# Generated deterministically by seda-macro-lef-normalizer-v1; recipe orfs-asap7-fakeram-m4-v1.
VERSION 5.8 ;
BUSBITCHARS "[]" ;
DIVIDERCHAR "/" ;

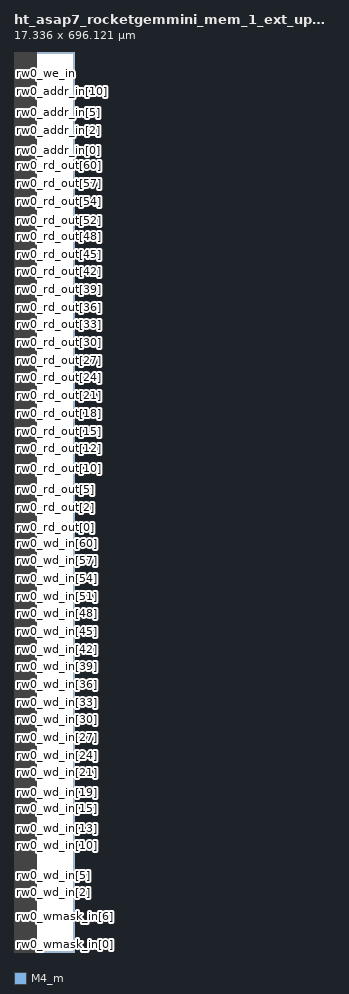
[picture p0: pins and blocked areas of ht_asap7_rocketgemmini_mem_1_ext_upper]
MACRO ht_asap7_rocketgemmini_mem_1_ext_upper
  FOREIGN ht_asap7_rocketgemmini_mem_1_ext_upper 0 0 ;
  CLASS COVER ;
  ORIGIN 0 0 ;
  SIZE 17.336 BY 696.121 ;
  SYMMETRY X Y R90 ;
  PIN rw0_wmask_in[0]
    DIRECTION INPUT ;
    USE SIGNAL ;
    SHAPE ABUTMENT ;
    PORT
      LAYER M4_m ;
      RECT 0 0.048 0.024 0.072 ;
    END
  END rw0_wmask_in[0]
  PIN rw0_wmask_in[1]
    DIRECTION INPUT ;
    USE SIGNAL ;
    SHAPE ABUTMENT ;
    PORT
      LAYER M4_m ;
      RECT 0 4.608 0.024 4.632 ;
    END
  END rw0_wmask_in[1]
  PIN rw0_wmask_in[2]
    DIRECTION INPUT ;
    USE SIGNAL ;
    SHAPE ABUTMENT ;
    PORT
      LAYER M4_m ;
      RECT 0 9.168 0.024 9.192 ;
    END
  END rw0_wmask_in[2]
  PIN rw0_wmask_in[3]
    DIRECTION INPUT ;
    USE SIGNAL ;
    SHAPE ABUTMENT ;
    PORT
      LAYER M4_m ;
      RECT 0 13.728 0.024 13.752 ;
    END
  END rw0_wmask_in[3]
  PIN rw0_wmask_in[4]
    DIRECTION INPUT ;
    USE SIGNAL ;
    SHAPE ABUTMENT ;
    PORT
      LAYER M4_m ;
      RECT 0 18.288 0.024 18.312 ;
    END
  END rw0_wmask_in[4]
  PIN rw0_wmask_in[5]
    DIRECTION INPUT ;
    USE SIGNAL ;
    SHAPE ABUTMENT ;
    PORT
      LAYER M4_m ;
      RECT 0 22.848 0.024 22.872 ;
    END
  END rw0_wmask_in[5]
  PIN rw0_wmask_in[6]
    DIRECTION INPUT ;
    USE SIGNAL ;
    SHAPE ABUTMENT ;
    PORT
      LAYER M4_m ;
      RECT 0 27.408 0.024 27.432 ;
    END
  END rw0_wmask_in[6]
  PIN rw0_wmask_in[7]
    DIRECTION INPUT ;
    USE SIGNAL ;
    SHAPE ABUTMENT ;
    PORT
      LAYER M4_m ;
      RECT 0 31.968 0.024 31.992 ;
    END
  END rw0_wmask_in[7]
  PIN rw0_wd_in[0]
    DIRECTION INPUT ;
    USE SIGNAL ;
    SHAPE ABUTMENT ;
    PORT
      LAYER M4_m ;
      RECT 0 36.528 0.024 36.552 ;
    END
  END rw0_wd_in[0]
  PIN rw0_wd_in[1]
    DIRECTION INPUT ;
    USE SIGNAL ;
    SHAPE ABUTMENT ;
    PORT
      LAYER M4_m ;
      RECT 0 41.088 0.024 41.112 ;
    END
  END rw0_wd_in[1]
  PIN rw0_wd_in[2]
    DIRECTION INPUT ;
    USE SIGNAL ;
    SHAPE ABUTMENT ;
    PORT
      LAYER M4_m ;
      RECT 0 45.648 0.024 45.672 ;
    END
  END rw0_wd_in[2]
  PIN rw0_wd_in[3]
    DIRECTION INPUT ;
    USE SIGNAL ;
    SHAPE ABUTMENT ;
    PORT
      LAYER M4_m ;
      RECT 0 50.208 0.024 50.232 ;
    END
  END rw0_wd_in[3]
  PIN rw0_wd_in[4]
    DIRECTION INPUT ;
    USE SIGNAL ;
    SHAPE ABUTMENT ;
    PORT
      LAYER M4_m ;
      RECT 0 54.768 0.024 54.792 ;
    END
  END rw0_wd_in[4]
  PIN rw0_wd_in[5]
    DIRECTION INPUT ;
    USE SIGNAL ;
    SHAPE ABUTMENT ;
    PORT
      LAYER M4_m ;
      RECT 0 59.328 0.024 59.352 ;
    END
  END rw0_wd_in[5]
  PIN rw0_wd_in[6]
    DIRECTION INPUT ;
    USE SIGNAL ;
    SHAPE ABUTMENT ;
    PORT
      LAYER M4_m ;
      RECT 0 63.888 0.024 63.912 ;
    END
  END rw0_wd_in[6]
  PIN rw0_wd_in[7]
    DIRECTION INPUT ;
    USE SIGNAL ;
    SHAPE ABUTMENT ;
    PORT
      LAYER M4_m ;
      RECT 0 68.448 0.024 68.472 ;
    END
  END rw0_wd_in[7]
  PIN rw0_wd_in[8]
    DIRECTION INPUT ;
    USE SIGNAL ;
    SHAPE ABUTMENT ;
    PORT
      LAYER M4_m ;
      RECT 0 73.008 0.024 73.032 ;
    END
  END rw0_wd_in[8]
  PIN rw0_wd_in[9]
    DIRECTION INPUT ;
    USE SIGNAL ;
    SHAPE ABUTMENT ;
    PORT
      LAYER M4_m ;
      RECT 0 77.568 0.024 77.592 ;
    END
  END rw0_wd_in[9]
  PIN rw0_wd_in[10]
    DIRECTION INPUT ;
    USE SIGNAL ;
    SHAPE ABUTMENT ;
    PORT
      LAYER M4_m ;
      RECT 0 82.128 0.024 82.152 ;
    END
  END rw0_wd_in[10]
  PIN rw0_wd_in[11]
    DIRECTION INPUT ;
    USE SIGNAL ;
    SHAPE ABUTMENT ;
    PORT
      LAYER M4_m ;
      RECT 0 86.688 0.024 86.712 ;
    END
  END rw0_wd_in[11]
  PIN rw0_wd_in[12]
    DIRECTION INPUT ;
    USE SIGNAL ;
    SHAPE ABUTMENT ;
    PORT
      LAYER M4_m ;
      RECT 0 91.248 0.024 91.272 ;
    END
  END rw0_wd_in[12]
  PIN rw0_wd_in[13]
    DIRECTION INPUT ;
    USE SIGNAL ;
    SHAPE ABUTMENT ;
    PORT
      LAYER M4_m ;
      RECT 0 95.808 0.024 95.832 ;
    END
  END rw0_wd_in[13]
  PIN rw0_wd_in[14]
    DIRECTION INPUT ;
    USE SIGNAL ;
    SHAPE ABUTMENT ;
    PORT
      LAYER M4_m ;
      RECT 0 100.368 0.024 100.392 ;
    END
  END rw0_wd_in[14]
  PIN rw0_wd_in[15]
    DIRECTION INPUT ;
    USE SIGNAL ;
    SHAPE ABUTMENT ;
    PORT
      LAYER M4_m ;
      RECT 0 104.928 0.024 104.952 ;
    END
  END rw0_wd_in[15]
  PIN rw0_wd_in[16]
    DIRECTION INPUT ;
    USE SIGNAL ;
    SHAPE ABUTMENT ;
    PORT
      LAYER M4_m ;
      RECT 0 109.488 0.024 109.512 ;
    END
  END rw0_wd_in[16]
  PIN rw0_wd_in[17]
    DIRECTION INPUT ;
    USE SIGNAL ;
    SHAPE ABUTMENT ;
    PORT
      LAYER M4_m ;
      RECT 0 114.048 0.024 114.072 ;
    END
  END rw0_wd_in[17]
  PIN rw0_wd_in[18]
    DIRECTION INPUT ;
    USE SIGNAL ;
    SHAPE ABUTMENT ;
    PORT
      LAYER M4_m ;
      RECT 0 118.608 0.024 118.632 ;
    END
  END rw0_wd_in[18]
  PIN rw0_wd_in[19]
    DIRECTION INPUT ;
    USE SIGNAL ;
    SHAPE ABUTMENT ;
    PORT
      LAYER M4_m ;
      RECT 0 123.168 0.024 123.192 ;
    END
  END rw0_wd_in[19]
  PIN rw0_wd_in[20]
    DIRECTION INPUT ;
    USE SIGNAL ;
    SHAPE ABUTMENT ;
    PORT
      LAYER M4_m ;
      RECT 0 127.728 0.024 127.752 ;
    END
  END rw0_wd_in[20]
  PIN rw0_wd_in[21]
    DIRECTION INPUT ;
    USE SIGNAL ;
    SHAPE ABUTMENT ;
    PORT
      LAYER M4_m ;
      RECT 0 132.288 0.024 132.312 ;
    END
  END rw0_wd_in[21]
  PIN rw0_wd_in[22]
    DIRECTION INPUT ;
    USE SIGNAL ;
    SHAPE ABUTMENT ;
    PORT
      LAYER M4_m ;
      RECT 0 136.848 0.024 136.872 ;
    END
  END rw0_wd_in[22]
  PIN rw0_wd_in[23]
    DIRECTION INPUT ;
    USE SIGNAL ;
    SHAPE ABUTMENT ;
    PORT
      LAYER M4_m ;
      RECT 0 141.408 0.024 141.432 ;
    END
  END rw0_wd_in[23]
  PIN rw0_wd_in[24]
    DIRECTION INPUT ;
    USE SIGNAL ;
    SHAPE ABUTMENT ;
    PORT
      LAYER M4_m ;
      RECT 0 145.968 0.024 145.992 ;
    END
  END rw0_wd_in[24]
  PIN rw0_wd_in[25]
    DIRECTION INPUT ;
    USE SIGNAL ;
    SHAPE ABUTMENT ;
    PORT
      LAYER M4_m ;
      RECT 0 150.528 0.024 150.552 ;
    END
  END rw0_wd_in[25]
  PIN rw0_wd_in[26]
    DIRECTION INPUT ;
    USE SIGNAL ;
    SHAPE ABUTMENT ;
    PORT
      LAYER M4_m ;
      RECT 0 155.088 0.024 155.112 ;
    END
  END rw0_wd_in[26]
  PIN rw0_wd_in[27]
    DIRECTION INPUT ;
    USE SIGNAL ;
    SHAPE ABUTMENT ;
    PORT
      LAYER M4_m ;
      RECT 0 159.648 0.024 159.672 ;
    END
  END rw0_wd_in[27]
  PIN rw0_wd_in[28]
    DIRECTION INPUT ;
    USE SIGNAL ;
    SHAPE ABUTMENT ;
    PORT
      LAYER M4_m ;
      RECT 0 164.208 0.024 164.232 ;
    END
  END rw0_wd_in[28]
  PIN rw0_wd_in[29]
    DIRECTION INPUT ;
    USE SIGNAL ;
    SHAPE ABUTMENT ;
    PORT
      LAYER M4_m ;
      RECT 0 168.768 0.024 168.792 ;
    END
  END rw0_wd_in[29]
  PIN rw0_wd_in[30]
    DIRECTION INPUT ;
    USE SIGNAL ;
    SHAPE ABUTMENT ;
    PORT
      LAYER M4_m ;
      RECT 0 173.328 0.024 173.352 ;
    END
  END rw0_wd_in[30]
  PIN rw0_wd_in[31]
    DIRECTION INPUT ;
    USE SIGNAL ;
    SHAPE ABUTMENT ;
    PORT
      LAYER M4_m ;
      RECT 0 177.888 0.024 177.912 ;
    END
  END rw0_wd_in[31]
  PIN rw0_wd_in[32]
    DIRECTION INPUT ;
    USE SIGNAL ;
    SHAPE ABUTMENT ;
    PORT
      LAYER M4_m ;
      RECT 0 182.448 0.024 182.472 ;
    END
  END rw0_wd_in[32]
  PIN rw0_wd_in[33]
    DIRECTION INPUT ;
    USE SIGNAL ;
    SHAPE ABUTMENT ;
    PORT
      LAYER M4_m ;
      RECT 0 187.008 0.024 187.032 ;
    END
  END rw0_wd_in[33]
  PIN rw0_wd_in[34]
    DIRECTION INPUT ;
    USE SIGNAL ;
    SHAPE ABUTMENT ;
    PORT
      LAYER M4_m ;
      RECT 0 191.568 0.024 191.592 ;
    END
  END rw0_wd_in[34]
  PIN rw0_wd_in[35]
    DIRECTION INPUT ;
    USE SIGNAL ;
    SHAPE ABUTMENT ;
    PORT
      LAYER M4_m ;
      RECT 0 196.128 0.024 196.152 ;
    END
  END rw0_wd_in[35]
  PIN rw0_wd_in[36]
    DIRECTION INPUT ;
    USE SIGNAL ;
    SHAPE ABUTMENT ;
    PORT
      LAYER M4_m ;
      RECT 0 200.688 0.024 200.712 ;
    END
  END rw0_wd_in[36]
  PIN rw0_wd_in[37]
    DIRECTION INPUT ;
    USE SIGNAL ;
    SHAPE ABUTMENT ;
    PORT
      LAYER M4_m ;
      RECT 0 205.248 0.024 205.272 ;
    END
  END rw0_wd_in[37]
  PIN rw0_wd_in[38]
    DIRECTION INPUT ;
    USE SIGNAL ;
    SHAPE ABUTMENT ;
    PORT
      LAYER M4_m ;
      RECT 0 209.808 0.024 209.832 ;
    END
  END rw0_wd_in[38]
  PIN rw0_wd_in[39]
    DIRECTION INPUT ;
    USE SIGNAL ;
    SHAPE ABUTMENT ;
    PORT
      LAYER M4_m ;
      RECT 0 214.368 0.024 214.392 ;
    END
  END rw0_wd_in[39]
  PIN rw0_wd_in[40]
    DIRECTION INPUT ;
    USE SIGNAL ;
    SHAPE ABUTMENT ;
    PORT
      LAYER M4_m ;
      RECT 0 218.928 0.024 218.952 ;
    END
  END rw0_wd_in[40]
  PIN rw0_wd_in[41]
    DIRECTION INPUT ;
    USE SIGNAL ;
    SHAPE ABUTMENT ;
    PORT
      LAYER M4_m ;
      RECT 0 223.488 0.024 223.512 ;
    END
  END rw0_wd_in[41]
  PIN rw0_wd_in[42]
    DIRECTION INPUT ;
    USE SIGNAL ;
    SHAPE ABUTMENT ;
    PORT
      LAYER M4_m ;
      RECT 0 228.048 0.024 228.072 ;
    END
  END rw0_wd_in[42]
  PIN rw0_wd_in[43]
    DIRECTION INPUT ;
    USE SIGNAL ;
    SHAPE ABUTMENT ;
    PORT
      LAYER M4_m ;
      RECT 0 232.608 0.024 232.632 ;
    END
  END rw0_wd_in[43]
  PIN rw0_wd_in[44]
    DIRECTION INPUT ;
    USE SIGNAL ;
    SHAPE ABUTMENT ;
    PORT
      LAYER M4_m ;
      RECT 0 237.168 0.024 237.192 ;
    END
  END rw0_wd_in[44]
  PIN rw0_wd_in[45]
    DIRECTION INPUT ;
    USE SIGNAL ;
    SHAPE ABUTMENT ;
    PORT
      LAYER M4_m ;
      RECT 0 241.728 0.024 241.752 ;
    END
  END rw0_wd_in[45]
  PIN rw0_wd_in[46]
    DIRECTION INPUT ;
    USE SIGNAL ;
    SHAPE ABUTMENT ;
    PORT
      LAYER M4_m ;
      RECT 0 246.288 0.024 246.312 ;
    END
  END rw0_wd_in[46]
  PIN rw0_wd_in[47]
    DIRECTION INPUT ;
    USE SIGNAL ;
    SHAPE ABUTMENT ;
    PORT
      LAYER M4_m ;
      RECT 0 250.848 0.024 250.872 ;
    END
  END rw0_wd_in[47]
  PIN rw0_wd_in[48]
    DIRECTION INPUT ;
    USE SIGNAL ;
    SHAPE ABUTMENT ;
    PORT
      LAYER M4_m ;
      RECT 0 255.408 0.024 255.432 ;
    END
  END rw0_wd_in[48]
  PIN rw0_wd_in[49]
    DIRECTION INPUT ;
    USE SIGNAL ;
    SHAPE ABUTMENT ;
    PORT
      LAYER M4_m ;
      RECT 0 259.968 0.024 259.992 ;
    END
  END rw0_wd_in[49]
  PIN rw0_wd_in[50]
    DIRECTION INPUT ;
    USE SIGNAL ;
    SHAPE ABUTMENT ;
    PORT
      LAYER M4_m ;
      RECT 0 264.528 0.024 264.552 ;
    END
  END rw0_wd_in[50]
  PIN rw0_wd_in[51]
    DIRECTION INPUT ;
    USE SIGNAL ;
    SHAPE ABUTMENT ;
    PORT
      LAYER M4_m ;
      RECT 0 269.088 0.024 269.112 ;
    END
  END rw0_wd_in[51]
  PIN rw0_wd_in[52]
    DIRECTION INPUT ;
    USE SIGNAL ;
    SHAPE ABUTMENT ;
    PORT
      LAYER M4_m ;
      RECT 0 273.648 0.024 273.672 ;
    END
  END rw0_wd_in[52]
  PIN rw0_wd_in[53]
    DIRECTION INPUT ;
    USE SIGNAL ;
    SHAPE ABUTMENT ;
    PORT
      LAYER M4_m ;
      RECT 0 278.208 0.024 278.232 ;
    END
  END rw0_wd_in[53]
  PIN rw0_wd_in[54]
    DIRECTION INPUT ;
    USE SIGNAL ;
    SHAPE ABUTMENT ;
    PORT
      LAYER M4_m ;
      RECT 0 282.768 0.024 282.792 ;
    END
  END rw0_wd_in[54]
  PIN rw0_wd_in[55]
    DIRECTION INPUT ;
    USE SIGNAL ;
    SHAPE ABUTMENT ;
    PORT
      LAYER M4_m ;
      RECT 0 287.328 0.024 287.352 ;
    END
  END rw0_wd_in[55]
  PIN rw0_wd_in[56]
    DIRECTION INPUT ;
    USE SIGNAL ;
    SHAPE ABUTMENT ;
    PORT
      LAYER M4_m ;
      RECT 0 291.888 0.024 291.912 ;
    END
  END rw0_wd_in[56]
  PIN rw0_wd_in[57]
    DIRECTION INPUT ;
    USE SIGNAL ;
    SHAPE ABUTMENT ;
    PORT
      LAYER M4_m ;
      RECT 0 296.448 0.024 296.472 ;
    END
  END rw0_wd_in[57]
  PIN rw0_wd_in[58]
    DIRECTION INPUT ;
    USE SIGNAL ;
    SHAPE ABUTMENT ;
    PORT
      LAYER M4_m ;
      RECT 0 301.008 0.024 301.032 ;
    END
  END rw0_wd_in[58]
  PIN rw0_wd_in[59]
    DIRECTION INPUT ;
    USE SIGNAL ;
    SHAPE ABUTMENT ;
    PORT
      LAYER M4_m ;
      RECT 0 305.568 0.024 305.592 ;
    END
  END rw0_wd_in[59]
  PIN rw0_wd_in[60]
    DIRECTION INPUT ;
    USE SIGNAL ;
    SHAPE ABUTMENT ;
    PORT
      LAYER M4_m ;
      RECT 0 310.128 0.024 310.152 ;
    END
  END rw0_wd_in[60]
  PIN rw0_wd_in[61]
    DIRECTION INPUT ;
    USE SIGNAL ;
    SHAPE ABUTMENT ;
    PORT
      LAYER M4_m ;
      RECT 0 314.688 0.024 314.712 ;
    END
  END rw0_wd_in[61]
  PIN rw0_wd_in[62]
    DIRECTION INPUT ;
    USE SIGNAL ;
    SHAPE ABUTMENT ;
    PORT
      LAYER M4_m ;
      RECT 0 319.248 0.024 319.272 ;
    END
  END rw0_wd_in[62]
  PIN rw0_wd_in[63]
    DIRECTION INPUT ;
    USE SIGNAL ;
    SHAPE ABUTMENT ;
    PORT
      LAYER M4_m ;
      RECT 0 323.808 0.024 323.832 ;
    END
  END rw0_wd_in[63]
  PIN rw0_rd_out[0]
    DIRECTION OUTPUT ;
    USE SIGNAL ;
    SHAPE ABUTMENT ;
    PORT
      LAYER M4_m ;
      RECT 0 328.368 0.024 328.392 ;
    END
  END rw0_rd_out[0]
  PIN rw0_rd_out[1]
    DIRECTION OUTPUT ;
    USE SIGNAL ;
    SHAPE ABUTMENT ;
    PORT
      LAYER M4_m ;
      RECT 0 332.928 0.024 332.952 ;
    END
  END rw0_rd_out[1]
  PIN rw0_rd_out[2]
    DIRECTION OUTPUT ;
    USE SIGNAL ;
    SHAPE ABUTMENT ;
    PORT
      LAYER M4_m ;
      RECT 0 337.488 0.024 337.512 ;
    END
  END rw0_rd_out[2]
  PIN rw0_rd_out[3]
    DIRECTION OUTPUT ;
    USE SIGNAL ;
    SHAPE ABUTMENT ;
    PORT
      LAYER M4_m ;
      RECT 0 342.048 0.024 342.072 ;
    END
  END rw0_rd_out[3]
  PIN rw0_rd_out[4]
    DIRECTION OUTPUT ;
    USE SIGNAL ;
    SHAPE ABUTMENT ;
    PORT
      LAYER M4_m ;
      RECT 0 346.608 0.024 346.632 ;
    END
  END rw0_rd_out[4]
  PIN rw0_rd_out[5]
    DIRECTION OUTPUT ;
    USE SIGNAL ;
    SHAPE ABUTMENT ;
    PORT
      LAYER M4_m ;
      RECT 0 351.168 0.024 351.192 ;
    END
  END rw0_rd_out[5]
  PIN rw0_rd_out[6]
    DIRECTION OUTPUT ;
    USE SIGNAL ;
    SHAPE ABUTMENT ;
    PORT
      LAYER M4_m ;
      RECT 0 355.728 0.024 355.752 ;
    END
  END rw0_rd_out[6]
  PIN rw0_rd_out[7]
    DIRECTION OUTPUT ;
    USE SIGNAL ;
    SHAPE ABUTMENT ;
    PORT
      LAYER M4_m ;
      RECT 0 360.288 0.024 360.312 ;
    END
  END rw0_rd_out[7]
  PIN rw0_rd_out[8]
    DIRECTION OUTPUT ;
    USE SIGNAL ;
    SHAPE ABUTMENT ;
    PORT
      LAYER M4_m ;
      RECT 0 364.848 0.024 364.872 ;
    END
  END rw0_rd_out[8]
  PIN rw0_rd_out[9]
    DIRECTION OUTPUT ;
    USE SIGNAL ;
    SHAPE ABUTMENT ;
    PORT
      LAYER M4_m ;
      RECT 0 369.408 0.024 369.432 ;
    END
  END rw0_rd_out[9]
  PIN rw0_rd_out[10]
    DIRECTION OUTPUT ;
    USE SIGNAL ;
    SHAPE ABUTMENT ;
    PORT
      LAYER M4_m ;
      RECT 0 373.968 0.024 373.992 ;
    END
  END rw0_rd_out[10]
  PIN rw0_rd_out[11]
    DIRECTION OUTPUT ;
    USE SIGNAL ;
    SHAPE ABUTMENT ;
    PORT
      LAYER M4_m ;
      RECT 0 378.528 0.024 378.552 ;
    END
  END rw0_rd_out[11]
  PIN rw0_rd_out[12]
    DIRECTION OUTPUT ;
    USE SIGNAL ;
    SHAPE ABUTMENT ;
    PORT
      LAYER M4_m ;
      RECT 0 383.088 0.024 383.112 ;
    END
  END rw0_rd_out[12]
  PIN rw0_rd_out[13]
    DIRECTION OUTPUT ;
    USE SIGNAL ;
    SHAPE ABUTMENT ;
    PORT
      LAYER M4_m ;
      RECT 0 387.648 0.024 387.672 ;
    END
  END rw0_rd_out[13]
  PIN rw0_rd_out[14]
    DIRECTION OUTPUT ;
    USE SIGNAL ;
    SHAPE ABUTMENT ;
    PORT
      LAYER M4_m ;
      RECT 0 392.208 0.024 392.232 ;
    END
  END rw0_rd_out[14]
  PIN rw0_rd_out[15]
    DIRECTION OUTPUT ;
    USE SIGNAL ;
    SHAPE ABUTMENT ;
    PORT
      LAYER M4_m ;
      RECT 0 396.768 0.024 396.792 ;
    END
  END rw0_rd_out[15]
  PIN rw0_rd_out[16]
    DIRECTION OUTPUT ;
    USE SIGNAL ;
    SHAPE ABUTMENT ;
    PORT
      LAYER M4_m ;
      RECT 0 401.328 0.024 401.352 ;
    END
  END rw0_rd_out[16]
  PIN rw0_rd_out[17]
    DIRECTION OUTPUT ;
    USE SIGNAL ;
    SHAPE ABUTMENT ;
    PORT
      LAYER M4_m ;
      RECT 0 405.888 0.024 405.912 ;
    END
  END rw0_rd_out[17]
  PIN rw0_rd_out[18]
    DIRECTION OUTPUT ;
    USE SIGNAL ;
    SHAPE ABUTMENT ;
    PORT
      LAYER M4_m ;
      RECT 0 410.448 0.024 410.472 ;
    END
  END rw0_rd_out[18]
  PIN rw0_rd_out[19]
    DIRECTION OUTPUT ;
    USE SIGNAL ;
    SHAPE ABUTMENT ;
    PORT
      LAYER M4_m ;
      RECT 0 415.008 0.024 415.032 ;
    END
  END rw0_rd_out[19]
  PIN rw0_rd_out[20]
    DIRECTION OUTPUT ;
    USE SIGNAL ;
    SHAPE ABUTMENT ;
    PORT
      LAYER M4_m ;
      RECT 0 419.568 0.024 419.592 ;
    END
  END rw0_rd_out[20]
  PIN rw0_rd_out[21]
    DIRECTION OUTPUT ;
    USE SIGNAL ;
    SHAPE ABUTMENT ;
    PORT
      LAYER M4_m ;
      RECT 0 424.128 0.024 424.152 ;
    END
  END rw0_rd_out[21]
  PIN rw0_rd_out[22]
    DIRECTION OUTPUT ;
    USE SIGNAL ;
    SHAPE ABUTMENT ;
    PORT
      LAYER M4_m ;
      RECT 0 428.688 0.024 428.712 ;
    END
  END rw0_rd_out[22]
  PIN rw0_rd_out[23]
    DIRECTION OUTPUT ;
    USE SIGNAL ;
    SHAPE ABUTMENT ;
    PORT
      LAYER M4_m ;
      RECT 0 433.248 0.024 433.272 ;
    END
  END rw0_rd_out[23]
  PIN rw0_rd_out[24]
    DIRECTION OUTPUT ;
    USE SIGNAL ;
    SHAPE ABUTMENT ;
    PORT
      LAYER M4_m ;
      RECT 0 437.808 0.024 437.832 ;
    END
  END rw0_rd_out[24]
  PIN rw0_rd_out[25]
    DIRECTION OUTPUT ;
    USE SIGNAL ;
    SHAPE ABUTMENT ;
    PORT
      LAYER M4_m ;
      RECT 0 442.368 0.024 442.392 ;
    END
  END rw0_rd_out[25]
  PIN rw0_rd_out[26]
    DIRECTION OUTPUT ;
    USE SIGNAL ;
    SHAPE ABUTMENT ;
    PORT
      LAYER M4_m ;
      RECT 0 446.928 0.024 446.952 ;
    END
  END rw0_rd_out[26]
  PIN rw0_rd_out[27]
    DIRECTION OUTPUT ;
    USE SIGNAL ;
    SHAPE ABUTMENT ;
    PORT
      LAYER M4_m ;
      RECT 0 451.488 0.024 451.512 ;
    END
  END rw0_rd_out[27]
  PIN rw0_rd_out[28]
    DIRECTION OUTPUT ;
    USE SIGNAL ;
    SHAPE ABUTMENT ;
    PORT
      LAYER M4_m ;
      RECT 0 456.048 0.024 456.072 ;
    END
  END rw0_rd_out[28]
  PIN rw0_rd_out[29]
    DIRECTION OUTPUT ;
    USE SIGNAL ;
    SHAPE ABUTMENT ;
    PORT
      LAYER M4_m ;
      RECT 0 460.608 0.024 460.632 ;
    END
  END rw0_rd_out[29]
  PIN rw0_rd_out[30]
    DIRECTION OUTPUT ;
    USE SIGNAL ;
    SHAPE ABUTMENT ;
    PORT
      LAYER M4_m ;
      RECT 0 465.168 0.024 465.192 ;
    END
  END rw0_rd_out[30]
  PIN rw0_rd_out[31]
    DIRECTION OUTPUT ;
    USE SIGNAL ;
    SHAPE ABUTMENT ;
    PORT
      LAYER M4_m ;
      RECT 0 469.728 0.024 469.752 ;
    END
  END rw0_rd_out[31]
  PIN rw0_rd_out[32]
    DIRECTION OUTPUT ;
    USE SIGNAL ;
    SHAPE ABUTMENT ;
    PORT
      LAYER M4_m ;
      RECT 0 474.288 0.024 474.312 ;
    END
  END rw0_rd_out[32]
  PIN rw0_rd_out[33]
    DIRECTION OUTPUT ;
    USE SIGNAL ;
    SHAPE ABUTMENT ;
    PORT
      LAYER M4_m ;
      RECT 0 478.848 0.024 478.872 ;
    END
  END rw0_rd_out[33]
  PIN rw0_rd_out[34]
    DIRECTION OUTPUT ;
    USE SIGNAL ;
    SHAPE ABUTMENT ;
    PORT
      LAYER M4_m ;
      RECT 0 483.408 0.024 483.432 ;
    END
  END rw0_rd_out[34]
  PIN rw0_rd_out[35]
    DIRECTION OUTPUT ;
    USE SIGNAL ;
    SHAPE ABUTMENT ;
    PORT
      LAYER M4_m ;
      RECT 0 487.968 0.024 487.992 ;
    END
  END rw0_rd_out[35]
  PIN rw0_rd_out[36]
    DIRECTION OUTPUT ;
    USE SIGNAL ;
    SHAPE ABUTMENT ;
    PORT
      LAYER M4_m ;
      RECT 0 492.528 0.024 492.552 ;
    END
  END rw0_rd_out[36]
  PIN rw0_rd_out[37]
    DIRECTION OUTPUT ;
    USE SIGNAL ;
    SHAPE ABUTMENT ;
    PORT
      LAYER M4_m ;
      RECT 0 497.088 0.024 497.112 ;
    END
  END rw0_rd_out[37]
  PIN rw0_rd_out[38]
    DIRECTION OUTPUT ;
    USE SIGNAL ;
    SHAPE ABUTMENT ;
    PORT
      LAYER M4_m ;
      RECT 0 501.648 0.024 501.672 ;
    END
  END rw0_rd_out[38]
  PIN rw0_rd_out[39]
    DIRECTION OUTPUT ;
    USE SIGNAL ;
    SHAPE ABUTMENT ;
    PORT
      LAYER M4_m ;
      RECT 0 506.208 0.024 506.232 ;
    END
  END rw0_rd_out[39]
  PIN rw0_rd_out[40]
    DIRECTION OUTPUT ;
    USE SIGNAL ;
    SHAPE ABUTMENT ;
    PORT
      LAYER M4_m ;
      RECT 0 510.768 0.024 510.792 ;
    END
  END rw0_rd_out[40]
  PIN rw0_rd_out[41]
    DIRECTION OUTPUT ;
    USE SIGNAL ;
    SHAPE ABUTMENT ;
    PORT
      LAYER M4_m ;
      RECT 0 515.328 0.024 515.352 ;
    END
  END rw0_rd_out[41]
  PIN rw0_rd_out[42]
    DIRECTION OUTPUT ;
    USE SIGNAL ;
    SHAPE ABUTMENT ;
    PORT
      LAYER M4_m ;
      RECT 0 519.888 0.024 519.912 ;
    END
  END rw0_rd_out[42]
  PIN rw0_rd_out[43]
    DIRECTION OUTPUT ;
    USE SIGNAL ;
    SHAPE ABUTMENT ;
    PORT
      LAYER M4_m ;
      RECT 0 524.448 0.024 524.472 ;
    END
  END rw0_rd_out[43]
  PIN rw0_rd_out[44]
    DIRECTION OUTPUT ;
    USE SIGNAL ;
    SHAPE ABUTMENT ;
    PORT
      LAYER M4_m ;
      RECT 0 529.008 0.024 529.032 ;
    END
  END rw0_rd_out[44]
  PIN rw0_rd_out[45]
    DIRECTION OUTPUT ;
    USE SIGNAL ;
    SHAPE ABUTMENT ;
    PORT
      LAYER M4_m ;
      RECT 0 533.568 0.024 533.592 ;
    END
  END rw0_rd_out[45]
  PIN rw0_rd_out[46]
    DIRECTION OUTPUT ;
    USE SIGNAL ;
    SHAPE ABUTMENT ;
    PORT
      LAYER M4_m ;
      RECT 0 538.128 0.024 538.152 ;
    END
  END rw0_rd_out[46]
  PIN rw0_rd_out[47]
    DIRECTION OUTPUT ;
    USE SIGNAL ;
    SHAPE ABUTMENT ;
    PORT
      LAYER M4_m ;
      RECT 0 542.688 0.024 542.712 ;
    END
  END rw0_rd_out[47]
  PIN rw0_rd_out[48]
    DIRECTION OUTPUT ;
    USE SIGNAL ;
    SHAPE ABUTMENT ;
    PORT
      LAYER M4_m ;
      RECT 0 547.248 0.024 547.272 ;
    END
  END rw0_rd_out[48]
  PIN rw0_rd_out[49]
    DIRECTION OUTPUT ;
    USE SIGNAL ;
    SHAPE ABUTMENT ;
    PORT
      LAYER M4_m ;
      RECT 0 551.808 0.024 551.832 ;
    END
  END rw0_rd_out[49]
  PIN rw0_rd_out[50]
    DIRECTION OUTPUT ;
    USE SIGNAL ;
    SHAPE ABUTMENT ;
    PORT
      LAYER M4_m ;
      RECT 0 556.368 0.024 556.392 ;
    END
  END rw0_rd_out[50]
  PIN rw0_rd_out[51]
    DIRECTION OUTPUT ;
    USE SIGNAL ;
    SHAPE ABUTMENT ;
    PORT
      LAYER M4_m ;
      RECT 0 560.928 0.024 560.952 ;
    END
  END rw0_rd_out[51]
  PIN rw0_rd_out[52]
    DIRECTION OUTPUT ;
    USE SIGNAL ;
    SHAPE ABUTMENT ;
    PORT
      LAYER M4_m ;
      RECT 0 565.488 0.024 565.512 ;
    END
  END rw0_rd_out[52]
  PIN rw0_rd_out[53]
    DIRECTION OUTPUT ;
    USE SIGNAL ;
    SHAPE ABUTMENT ;
    PORT
      LAYER M4_m ;
      RECT 0 570.048 0.024 570.072 ;
    END
  END rw0_rd_out[53]
  PIN rw0_rd_out[54]
    DIRECTION OUTPUT ;
    USE SIGNAL ;
    SHAPE ABUTMENT ;
    PORT
      LAYER M4_m ;
      RECT 0 574.608 0.024 574.632 ;
    END
  END rw0_rd_out[54]
  PIN rw0_rd_out[55]
    DIRECTION OUTPUT ;
    USE SIGNAL ;
    SHAPE ABUTMENT ;
    PORT
      LAYER M4_m ;
      RECT 0 579.168 0.024 579.192 ;
    END
  END rw0_rd_out[55]
  PIN rw0_rd_out[56]
    DIRECTION OUTPUT ;
    USE SIGNAL ;
    SHAPE ABUTMENT ;
    PORT
      LAYER M4_m ;
      RECT 0 583.728 0.024 583.752 ;
    END
  END rw0_rd_out[56]
  PIN rw0_rd_out[57]
    DIRECTION OUTPUT ;
    USE SIGNAL ;
    SHAPE ABUTMENT ;
    PORT
      LAYER M4_m ;
      RECT 0 588.288 0.024 588.312 ;
    END
  END rw0_rd_out[57]
  PIN rw0_rd_out[58]
    DIRECTION OUTPUT ;
    USE SIGNAL ;
    SHAPE ABUTMENT ;
    PORT
      LAYER M4_m ;
      RECT 0 592.848 0.024 592.872 ;
    END
  END rw0_rd_out[58]
  PIN rw0_rd_out[59]
    DIRECTION OUTPUT ;
    USE SIGNAL ;
    SHAPE ABUTMENT ;
    PORT
      LAYER M4_m ;
      RECT 0 597.408 0.024 597.432 ;
    END
  END rw0_rd_out[59]
  PIN rw0_rd_out[60]
    DIRECTION OUTPUT ;
    USE SIGNAL ;
    SHAPE ABUTMENT ;
    PORT
      LAYER M4_m ;
      RECT 0 601.968 0.024 601.992 ;
    END
  END rw0_rd_out[60]
  PIN rw0_rd_out[61]
    DIRECTION OUTPUT ;
    USE SIGNAL ;
    SHAPE ABUTMENT ;
    PORT
      LAYER M4_m ;
      RECT 0 606.528 0.024 606.552 ;
    END
  END rw0_rd_out[61]
  PIN rw0_rd_out[62]
    DIRECTION OUTPUT ;
    USE SIGNAL ;
    SHAPE ABUTMENT ;
    PORT
      LAYER M4_m ;
      RECT 0 611.088 0.024 611.112 ;
    END
  END rw0_rd_out[62]
  PIN rw0_rd_out[63]
    DIRECTION OUTPUT ;
    USE SIGNAL ;
    SHAPE ABUTMENT ;
    PORT
      LAYER M4_m ;
      RECT 0 615.648 0.024 615.672 ;
    END
  END rw0_rd_out[63]
  PIN rw0_addr_in[0]
    DIRECTION INPUT ;
    USE SIGNAL ;
    SHAPE ABUTMENT ;
    PORT
      LAYER M4_m ;
      RECT 0 620.208 0.024 620.232 ;
    END
  END rw0_addr_in[0]
  PIN rw0_addr_in[1]
    DIRECTION INPUT ;
    USE SIGNAL ;
    SHAPE ABUTMENT ;
    PORT
      LAYER M4_m ;
      RECT 0 624.768 0.024 624.792 ;
    END
  END rw0_addr_in[1]
  PIN rw0_addr_in[2]
    DIRECTION INPUT ;
    USE SIGNAL ;
    SHAPE ABUTMENT ;
    PORT
      LAYER M4_m ;
      RECT 0 629.328 0.024 629.352 ;
    END
  END rw0_addr_in[2]
  PIN rw0_addr_in[3]
    DIRECTION INPUT ;
    USE SIGNAL ;
    SHAPE ABUTMENT ;
    PORT
      LAYER M4_m ;
      RECT 0 633.888 0.024 633.912 ;
    END
  END rw0_addr_in[3]
  PIN rw0_addr_in[4]
    DIRECTION INPUT ;
    USE SIGNAL ;
    SHAPE ABUTMENT ;
    PORT
      LAYER M4_m ;
      RECT 0 638.448 0.024 638.472 ;
    END
  END rw0_addr_in[4]
  PIN rw0_addr_in[5]
    DIRECTION INPUT ;
    USE SIGNAL ;
    SHAPE ABUTMENT ;
    PORT
      LAYER M4_m ;
      RECT 0 643.008 0.024 643.032 ;
    END
  END rw0_addr_in[5]
  PIN rw0_addr_in[6]
    DIRECTION INPUT ;
    USE SIGNAL ;
    SHAPE ABUTMENT ;
    PORT
      LAYER M4_m ;
      RECT 0 647.568 0.024 647.592 ;
    END
  END rw0_addr_in[6]
  PIN rw0_addr_in[7]
    DIRECTION INPUT ;
    USE SIGNAL ;
    SHAPE ABUTMENT ;
    PORT
      LAYER M4_m ;
      RECT 0 652.128 0.024 652.152 ;
    END
  END rw0_addr_in[7]
  PIN rw0_addr_in[8]
    DIRECTION INPUT ;
    USE SIGNAL ;
    SHAPE ABUTMENT ;
    PORT
      LAYER M4_m ;
      RECT 0 656.688 0.024 656.712 ;
    END
  END rw0_addr_in[8]
  PIN rw0_addr_in[9]
    DIRECTION INPUT ;
    USE SIGNAL ;
    SHAPE ABUTMENT ;
    PORT
      LAYER M4_m ;
      RECT 0 661.248 0.024 661.272 ;
    END
  END rw0_addr_in[9]
  PIN rw0_addr_in[10]
    DIRECTION INPUT ;
    USE SIGNAL ;
    SHAPE ABUTMENT ;
    PORT
      LAYER M4_m ;
      RECT 0 665.808 0.024 665.832 ;
    END
  END rw0_addr_in[10]
  PIN rw0_addr_in[11]
    DIRECTION INPUT ;
    USE SIGNAL ;
    SHAPE ABUTMENT ;
    PORT
      LAYER M4_m ;
      RECT 0 670.368 0.024 670.392 ;
    END
  END rw0_addr_in[11]
  PIN rw0_addr_in[12]
    DIRECTION INPUT ;
    USE SIGNAL ;
    SHAPE ABUTMENT ;
    PORT
      LAYER M4_m ;
      RECT 0 674.928 0.024 674.952 ;
    END
  END rw0_addr_in[12]
  PIN rw0_we_in
    DIRECTION INPUT ;
    USE SIGNAL ;
    SHAPE ABUTMENT ;
    PORT
      LAYER M4_m ;
      RECT 0 679.488 0.024 679.512 ;
    END
  END rw0_we_in
  PIN rw0_ce_in
    DIRECTION INPUT ;
    USE SIGNAL ;
    SHAPE ABUTMENT ;
    PORT
      LAYER M4_m ;
      RECT 0 684.048 0.024 684.072 ;
    END
  END rw0_ce_in
  PIN rw0_clk
    DIRECTION INPUT ;
    USE SIGNAL ;
    SHAPE ABUTMENT ;
    PORT
      LAYER M4_m ;
      RECT 0 688.608 0.024 688.632 ;
    END
  END rw0_clk
  PIN VSS
    DIRECTION INOUT ;
    USE GROUND ;
    PORT
      LAYER M4_m ;
      RECT 0.048 0 17.288 0.096 ;
      RECT 0.048 0.768 17.288 0.864 ;
      RECT 0.048 1.536 17.288 1.632 ;
      RECT 0.048 2.304 17.288 2.4 ;
      RECT 0.048 3.072 17.288 3.168 ;
      RECT 0.048 3.84 17.288 3.936 ;
      RECT 0.048 4.608 17.288 4.704 ;
      RECT 0.048 5.376 17.288 5.472 ;
      RECT 0.048 6.144 17.288 6.24 ;
      RECT 0.048 6.912 17.288 7.008 ;
      RECT 0.048 7.68 17.288 7.776 ;
      RECT 0.048 8.448 17.288 8.544 ;
      RECT 0.048 9.216 17.288 9.312 ;
      RECT 0.048 9.984 17.288 10.08 ;
      RECT 0.048 10.752 17.288 10.848 ;
      RECT 0.048 11.52 17.288 11.616 ;
      RECT 0.048 12.288 17.288 12.384 ;
      RECT 0.048 13.056 17.288 13.152 ;
      RECT 0.048 13.824 17.288 13.92 ;
      RECT 0.048 14.592 17.288 14.688 ;
      RECT 0.048 15.36 17.288 15.456 ;
      RECT 0.048 16.128 17.288 16.224 ;
      RECT 0.048 16.896 17.288 16.992 ;
      RECT 0.048 17.664 17.288 17.76 ;
      RECT 0.048 18.432 17.288 18.528 ;
      RECT 0.048 19.2 17.288 19.296 ;
      RECT 0.048 19.968 17.288 20.064 ;
      RECT 0.048 20.736 17.288 20.832 ;
      RECT 0.048 21.504 17.288 21.6 ;
      RECT 0.048 22.272 17.288 22.368 ;
      RECT 0.048 23.04 17.288 23.136 ;
      RECT 0.048 23.808 17.288 23.904 ;
      RECT 0.048 24.576 17.288 24.672 ;
      RECT 0.048 25.344 17.288 25.44 ;
      RECT 0.048 26.112 17.288 26.208 ;
      RECT 0.048 26.88 17.288 26.976 ;
      RECT 0.048 27.648 17.288 27.744 ;
      RECT 0.048 28.416 17.288 28.512 ;
      RECT 0.048 29.184 17.288 29.28 ;
      RECT 0.048 29.952 17.288 30.048 ;
      RECT 0.048 30.72 17.288 30.816 ;
      RECT 0.048 31.488 17.288 31.584 ;
      RECT 0.048 32.256 17.288 32.352 ;
      RECT 0.048 33.024 17.288 33.12 ;
      RECT 0.048 33.792 17.288 33.888 ;
      RECT 0.048 34.56 17.288 34.656 ;
      RECT 0.048 35.328 17.288 35.424 ;
      RECT 0.048 36.096 17.288 36.192 ;
      RECT 0.048 36.864 17.288 36.96 ;
      RECT 0.048 37.632 17.288 37.728 ;
      RECT 0.048 38.4 17.288 38.496 ;
      RECT 0.048 39.168 17.288 39.264 ;
      RECT 0.048 39.936 17.288 40.032 ;
      RECT 0.048 40.704 17.288 40.8 ;
      RECT 0.048 41.472 17.288 41.568 ;
      RECT 0.048 42.24 17.288 42.336 ;
      RECT 0.048 43.008 17.288 43.104 ;
      RECT 0.048 43.776 17.288 43.872 ;
      RECT 0.048 44.544 17.288 44.64 ;
      RECT 0.048 45.312 17.288 45.408 ;
      RECT 0.048 46.08 17.288 46.176 ;
      RECT 0.048 46.848 17.288 46.944 ;
      RECT 0.048 47.616 17.288 47.712 ;
      RECT 0.048 48.384 17.288 48.48 ;
      RECT 0.048 49.152 17.288 49.248 ;
      RECT 0.048 49.92 17.288 50.016 ;
      RECT 0.048 50.688 17.288 50.784 ;
      RECT 0.048 51.456 17.288 51.552 ;
      RECT 0.048 52.224 17.288 52.32 ;
      RECT 0.048 52.992 17.288 53.088 ;
      RECT 0.048 53.76 17.288 53.856 ;
      RECT 0.048 54.528 17.288 54.624 ;
      RECT 0.048 55.296 17.288 55.392 ;
      RECT 0.048 56.064 17.288 56.16 ;
      RECT 0.048 56.832 17.288 56.928 ;
      RECT 0.048 57.6 17.288 57.696 ;
      RECT 0.048 58.368 17.288 58.464 ;
      RECT 0.048 59.136 17.288 59.232 ;
      RECT 0.048 59.904 17.288 60 ;
      RECT 0.048 60.672 17.288 60.768 ;
      RECT 0.048 61.44 17.288 61.536 ;
      RECT 0.048 62.208 17.288 62.304 ;
      RECT 0.048 62.976 17.288 63.072 ;
      RECT 0.048 63.744 17.288 63.84 ;
      RECT 0.048 64.512 17.288 64.608 ;
      RECT 0.048 65.28 17.288 65.376 ;
      RECT 0.048 66.048 17.288 66.144 ;
      RECT 0.048 66.816 17.288 66.912 ;
      RECT 0.048 67.584 17.288 67.68 ;
      RECT 0.048 68.352 17.288 68.448 ;
      RECT 0.048 69.12 17.288 69.216 ;
      RECT 0.048 69.888 17.288 69.984 ;
      RECT 0.048 70.656 17.288 70.752 ;
      RECT 0.048 71.424 17.288 71.52 ;
      RECT 0.048 72.192 17.288 72.288 ;
      RECT 0.048 72.96 17.288 73.056 ;
      RECT 0.048 73.728 17.288 73.824 ;
      RECT 0.048 74.496 17.288 74.592 ;
      RECT 0.048 75.264 17.288 75.36 ;
      RECT 0.048 76.032 17.288 76.128 ;
      RECT 0.048 76.8 17.288 76.896 ;
      RECT 0.048 77.568 17.288 77.664 ;
      RECT 0.048 78.336 17.288 78.432 ;
      RECT 0.048 79.104 17.288 79.2 ;
      RECT 0.048 79.872 17.288 79.968 ;
      RECT 0.048 80.64 17.288 80.736 ;
      RECT 0.048 81.408 17.288 81.504 ;
      RECT 0.048 82.176 17.288 82.272 ;
      RECT 0.048 82.944 17.288 83.04 ;
      RECT 0.048 83.712 17.288 83.808 ;
      RECT 0.048 84.48 17.288 84.576 ;
      RECT 0.048 85.248 17.288 85.344 ;
      RECT 0.048 86.016 17.288 86.112 ;
      RECT 0.048 86.784 17.288 86.88 ;
      RECT 0.048 87.552 17.288 87.648 ;
      RECT 0.048 88.32 17.288 88.416 ;
      RECT 0.048 89.088 17.288 89.184 ;
      RECT 0.048 89.856 17.288 89.952 ;
      RECT 0.048 90.624 17.288 90.72 ;
      RECT 0.048 91.392 17.288 91.488 ;
      RECT 0.048 92.16 17.288 92.256 ;
      RECT 0.048 92.928 17.288 93.024 ;
      RECT 0.048 93.696 17.288 93.792 ;
      RECT 0.048 94.464 17.288 94.56 ;
      RECT 0.048 95.232 17.288 95.328 ;
      RECT 0.048 96 17.288 96.096 ;
      RECT 0.048 96.768 17.288 96.864 ;
      RECT 0.048 97.536 17.288 97.632 ;
      RECT 0.048 98.304 17.288 98.4 ;
      RECT 0.048 99.072 17.288 99.168 ;
      RECT 0.048 99.84 17.288 99.936 ;
      RECT 0.048 100.608 17.288 100.704 ;
      RECT 0.048 101.376 17.288 101.472 ;
      RECT 0.048 102.144 17.288 102.24 ;
      RECT 0.048 102.912 17.288 103.008 ;
      RECT 0.048 103.68 17.288 103.776 ;
      RECT 0.048 104.448 17.288 104.544 ;
      RECT 0.048 105.216 17.288 105.312 ;
      RECT 0.048 105.984 17.288 106.08 ;
      RECT 0.048 106.752 17.288 106.848 ;
      RECT 0.048 107.52 17.288 107.616 ;
      RECT 0.048 108.288 17.288 108.384 ;
      RECT 0.048 109.056 17.288 109.152 ;
      RECT 0.048 109.824 17.288 109.92 ;
      RECT 0.048 110.592 17.288 110.688 ;
      RECT 0.048 111.36 17.288 111.456 ;
      RECT 0.048 112.128 17.288 112.224 ;
      RECT 0.048 112.896 17.288 112.992 ;
      RECT 0.048 113.664 17.288 113.76 ;
      RECT 0.048 114.432 17.288 114.528 ;
      RECT 0.048 115.2 17.288 115.296 ;
      RECT 0.048 115.968 17.288 116.064 ;
      RECT 0.048 116.736 17.288 116.832 ;
      RECT 0.048 117.504 17.288 117.6 ;
      RECT 0.048 118.272 17.288 118.368 ;
      RECT 0.048 119.04 17.288 119.136 ;
      RECT 0.048 119.808 17.288 119.904 ;
      RECT 0.048 120.576 17.288 120.672 ;
      RECT 0.048 121.344 17.288 121.44 ;
      RECT 0.048 122.112 17.288 122.208 ;
      RECT 0.048 122.88 17.288 122.976 ;
      RECT 0.048 123.648 17.288 123.744 ;
      RECT 0.048 124.416 17.288 124.512 ;
      RECT 0.048 125.184 17.288 125.28 ;
      RECT 0.048 125.952 17.288 126.048 ;
      RECT 0.048 126.72 17.288 126.816 ;
      RECT 0.048 127.488 17.288 127.584 ;
      RECT 0.048 128.256 17.288 128.352 ;
      RECT 0.048 129.024 17.288 129.12 ;
      RECT 0.048 129.792 17.288 129.888 ;
      RECT 0.048 130.56 17.288 130.656 ;
      RECT 0.048 131.328 17.288 131.424 ;
      RECT 0.048 132.096 17.288 132.192 ;
      RECT 0.048 132.864 17.288 132.96 ;
      RECT 0.048 133.632 17.288 133.728 ;
      RECT 0.048 134.4 17.288 134.496 ;
      RECT 0.048 135.168 17.288 135.264 ;
      RECT 0.048 135.936 17.288 136.032 ;
      RECT 0.048 136.704 17.288 136.8 ;
      RECT 0.048 137.472 17.288 137.568 ;
      RECT 0.048 138.24 17.288 138.336 ;
      RECT 0.048 139.008 17.288 139.104 ;
      RECT 0.048 139.776 17.288 139.872 ;
      RECT 0.048 140.544 17.288 140.64 ;
      RECT 0.048 141.312 17.288 141.408 ;
      RECT 0.048 142.08 17.288 142.176 ;
      RECT 0.048 142.848 17.288 142.944 ;
      RECT 0.048 143.616 17.288 143.712 ;
      RECT 0.048 144.384 17.288 144.48 ;
      RECT 0.048 145.152 17.288 145.248 ;
      RECT 0.048 145.92 17.288 146.016 ;
      RECT 0.048 146.688 17.288 146.784 ;
      RECT 0.048 147.456 17.288 147.552 ;
      RECT 0.048 148.224 17.288 148.32 ;
      RECT 0.048 148.992 17.288 149.088 ;
      RECT 0.048 149.76 17.288 149.856 ;
      RECT 0.048 150.528 17.288 150.624 ;
      RECT 0.048 151.296 17.288 151.392 ;
      RECT 0.048 152.064 17.288 152.16 ;
      RECT 0.048 152.832 17.288 152.928 ;
      RECT 0.048 153.6 17.288 153.696 ;
      RECT 0.048 154.368 17.288 154.464 ;
      RECT 0.048 155.136 17.288 155.232 ;
      RECT 0.048 155.904 17.288 156 ;
      RECT 0.048 156.672 17.288 156.768 ;
      RECT 0.048 157.44 17.288 157.536 ;
      RECT 0.048 158.208 17.288 158.304 ;
      RECT 0.048 158.976 17.288 159.072 ;
      RECT 0.048 159.744 17.288 159.84 ;
      RECT 0.048 160.512 17.288 160.608 ;
      RECT 0.048 161.28 17.288 161.376 ;
      RECT 0.048 162.048 17.288 162.144 ;
      RECT 0.048 162.816 17.288 162.912 ;
      RECT 0.048 163.584 17.288 163.68 ;
      RECT 0.048 164.352 17.288 164.448 ;
      RECT 0.048 165.12 17.288 165.216 ;
      RECT 0.048 165.888 17.288 165.984 ;
      RECT 0.048 166.656 17.288 166.752 ;
      RECT 0.048 167.424 17.288 167.52 ;
      RECT 0.048 168.192 17.288 168.288 ;
      RECT 0.048 168.96 17.288 169.056 ;
      RECT 0.048 169.728 17.288 169.824 ;
      RECT 0.048 170.496 17.288 170.592 ;
      RECT 0.048 171.264 17.288 171.36 ;
      RECT 0.048 172.032 17.288 172.128 ;
      RECT 0.048 172.8 17.288 172.896 ;
      RECT 0.048 173.568 17.288 173.664 ;
      RECT 0.048 174.336 17.288 174.432 ;
      RECT 0.048 175.104 17.288 175.2 ;
      RECT 0.048 175.872 17.288 175.968 ;
      RECT 0.048 176.64 17.288 176.736 ;
      RECT 0.048 177.408 17.288 177.504 ;
      RECT 0.048 178.176 17.288 178.272 ;
      RECT 0.048 178.944 17.288 179.04 ;
      RECT 0.048 179.712 17.288 179.808 ;
      RECT 0.048 180.48 17.288 180.576 ;
      RECT 0.048 181.248 17.288 181.344 ;
      RECT 0.048 182.016 17.288 182.112 ;
      RECT 0.048 182.784 17.288 182.88 ;
      RECT 0.048 183.552 17.288 183.648 ;
      RECT 0.048 184.32 17.288 184.416 ;
      RECT 0.048 185.088 17.288 185.184 ;
      RECT 0.048 185.856 17.288 185.952 ;
      RECT 0.048 186.624 17.288 186.72 ;
      RECT 0.048 187.392 17.288 187.488 ;
      RECT 0.048 188.16 17.288 188.256 ;
      RECT 0.048 188.928 17.288 189.024 ;
      RECT 0.048 189.696 17.288 189.792 ;
      RECT 0.048 190.464 17.288 190.56 ;
      RECT 0.048 191.232 17.288 191.328 ;
      RECT 0.048 192 17.288 192.096 ;
      RECT 0.048 192.768 17.288 192.864 ;
      RECT 0.048 193.536 17.288 193.632 ;
      RECT 0.048 194.304 17.288 194.4 ;
      RECT 0.048 195.072 17.288 195.168 ;
      RECT 0.048 195.84 17.288 195.936 ;
      RECT 0.048 196.608 17.288 196.704 ;
      RECT 0.048 197.376 17.288 197.472 ;
      RECT 0.048 198.144 17.288 198.24 ;
      RECT 0.048 198.912 17.288 199.008 ;
      RECT 0.048 199.68 17.288 199.776 ;
      RECT 0.048 200.448 17.288 200.544 ;
      RECT 0.048 201.216 17.288 201.312 ;
      RECT 0.048 201.984 17.288 202.08 ;
      RECT 0.048 202.752 17.288 202.848 ;
      RECT 0.048 203.52 17.288 203.616 ;
      RECT 0.048 204.288 17.288 204.384 ;
      RECT 0.048 205.056 17.288 205.152 ;
      RECT 0.048 205.824 17.288 205.92 ;
      RECT 0.048 206.592 17.288 206.688 ;
      RECT 0.048 207.36 17.288 207.456 ;
      RECT 0.048 208.128 17.288 208.224 ;
      RECT 0.048 208.896 17.288 208.992 ;
      RECT 0.048 209.664 17.288 209.76 ;
      RECT 0.048 210.432 17.288 210.528 ;
      RECT 0.048 211.2 17.288 211.296 ;
      RECT 0.048 211.968 17.288 212.064 ;
      RECT 0.048 212.736 17.288 212.832 ;
      RECT 0.048 213.504 17.288 213.6 ;
      RECT 0.048 214.272 17.288 214.368 ;
      RECT 0.048 215.04 17.288 215.136 ;
      RECT 0.048 215.808 17.288 215.904 ;
      RECT 0.048 216.576 17.288 216.672 ;
      RECT 0.048 217.344 17.288 217.44 ;
      RECT 0.048 218.112 17.288 218.208 ;
      RECT 0.048 218.88 17.288 218.976 ;
      RECT 0.048 219.648 17.288 219.744 ;
      RECT 0.048 220.416 17.288 220.512 ;
      RECT 0.048 221.184 17.288 221.28 ;
      RECT 0.048 221.952 17.288 222.048 ;
      RECT 0.048 222.72 17.288 222.816 ;
      RECT 0.048 223.488 17.288 223.584 ;
      RECT 0.048 224.256 17.288 224.352 ;
      RECT 0.048 225.024 17.288 225.12 ;
      RECT 0.048 225.792 17.288 225.888 ;
      RECT 0.048 226.56 17.288 226.656 ;
      RECT 0.048 227.328 17.288 227.424 ;
      RECT 0.048 228.096 17.288 228.192 ;
      RECT 0.048 228.864 17.288 228.96 ;
      RECT 0.048 229.632 17.288 229.728 ;
      RECT 0.048 230.4 17.288 230.496 ;
      RECT 0.048 231.168 17.288 231.264 ;
      RECT 0.048 231.936 17.288 232.032 ;
      RECT 0.048 232.704 17.288 232.8 ;
      RECT 0.048 233.472 17.288 233.568 ;
      RECT 0.048 234.24 17.288 234.336 ;
      RECT 0.048 235.008 17.288 235.104 ;
      RECT 0.048 235.776 17.288 235.872 ;
      RECT 0.048 236.544 17.288 236.64 ;
      RECT 0.048 237.312 17.288 237.408 ;
      RECT 0.048 238.08 17.288 238.176 ;
      RECT 0.048 238.848 17.288 238.944 ;
      RECT 0.048 239.616 17.288 239.712 ;
      RECT 0.048 240.384 17.288 240.48 ;
      RECT 0.048 241.152 17.288 241.248 ;
      RECT 0.048 241.92 17.288 242.016 ;
      RECT 0.048 242.688 17.288 242.784 ;
      RECT 0.048 243.456 17.288 243.552 ;
      RECT 0.048 244.224 17.288 244.32 ;
      RECT 0.048 244.992 17.288 245.088 ;
      RECT 0.048 245.76 17.288 245.856 ;
      RECT 0.048 246.528 17.288 246.624 ;
      RECT 0.048 247.296 17.288 247.392 ;
      RECT 0.048 248.064 17.288 248.16 ;
      RECT 0.048 248.832 17.288 248.928 ;
      RECT 0.048 249.6 17.288 249.696 ;
      RECT 0.048 250.368 17.288 250.464 ;
      RECT 0.048 251.136 17.288 251.232 ;
      RECT 0.048 251.904 17.288 252 ;
      RECT 0.048 252.672 17.288 252.768 ;
      RECT 0.048 253.44 17.288 253.536 ;
      RECT 0.048 254.208 17.288 254.304 ;
      RECT 0.048 254.976 17.288 255.072 ;
      RECT 0.048 255.744 17.288 255.84 ;
      RECT 0.048 256.512 17.288 256.608 ;
      RECT 0.048 257.28 17.288 257.376 ;
      RECT 0.048 258.048 17.288 258.144 ;
      RECT 0.048 258.816 17.288 258.912 ;
      RECT 0.048 259.584 17.288 259.68 ;
      RECT 0.048 260.352 17.288 260.448 ;
      RECT 0.048 261.12 17.288 261.216 ;
      RECT 0.048 261.888 17.288 261.984 ;
      RECT 0.048 262.656 17.288 262.752 ;
      RECT 0.048 263.424 17.288 263.52 ;
      RECT 0.048 264.192 17.288 264.288 ;
      RECT 0.048 264.96 17.288 265.056 ;
      RECT 0.048 265.728 17.288 265.824 ;
      RECT 0.048 266.496 17.288 266.592 ;
      RECT 0.048 267.264 17.288 267.36 ;
      RECT 0.048 268.032 17.288 268.128 ;
      RECT 0.048 268.8 17.288 268.896 ;
      RECT 0.048 269.568 17.288 269.664 ;
      RECT 0.048 270.336 17.288 270.432 ;
      RECT 0.048 271.104 17.288 271.2 ;
      RECT 0.048 271.872 17.288 271.968 ;
      RECT 0.048 272.64 17.288 272.736 ;
      RECT 0.048 273.408 17.288 273.504 ;
      RECT 0.048 274.176 17.288 274.272 ;
      RECT 0.048 274.944 17.288 275.04 ;
      RECT 0.048 275.712 17.288 275.808 ;
      RECT 0.048 276.48 17.288 276.576 ;
      RECT 0.048 277.248 17.288 277.344 ;
      RECT 0.048 278.016 17.288 278.112 ;
      RECT 0.048 278.784 17.288 278.88 ;
      RECT 0.048 279.552 17.288 279.648 ;
      RECT 0.048 280.32 17.288 280.416 ;
      RECT 0.048 281.088 17.288 281.184 ;
      RECT 0.048 281.856 17.288 281.952 ;
      RECT 0.048 282.624 17.288 282.72 ;
      RECT 0.048 283.392 17.288 283.488 ;
      RECT 0.048 284.16 17.288 284.256 ;
      RECT 0.048 284.928 17.288 285.024 ;
      RECT 0.048 285.696 17.288 285.792 ;
      RECT 0.048 286.464 17.288 286.56 ;
      RECT 0.048 287.232 17.288 287.328 ;
      RECT 0.048 288 17.288 288.096 ;
      RECT 0.048 288.768 17.288 288.864 ;
      RECT 0.048 289.536 17.288 289.632 ;
      RECT 0.048 290.304 17.288 290.4 ;
      RECT 0.048 291.072 17.288 291.168 ;
      RECT 0.048 291.84 17.288 291.936 ;
      RECT 0.048 292.608 17.288 292.704 ;
      RECT 0.048 293.376 17.288 293.472 ;
      RECT 0.048 294.144 17.288 294.24 ;
      RECT 0.048 294.912 17.288 295.008 ;
      RECT 0.048 295.68 17.288 295.776 ;
      RECT 0.048 296.448 17.288 296.544 ;
      RECT 0.048 297.216 17.288 297.312 ;
      RECT 0.048 297.984 17.288 298.08 ;
      RECT 0.048 298.752 17.288 298.848 ;
      RECT 0.048 299.52 17.288 299.616 ;
      RECT 0.048 300.288 17.288 300.384 ;
      RECT 0.048 301.056 17.288 301.152 ;
      RECT 0.048 301.824 17.288 301.92 ;
      RECT 0.048 302.592 17.288 302.688 ;
      RECT 0.048 303.36 17.288 303.456 ;
      RECT 0.048 304.128 17.288 304.224 ;
      RECT 0.048 304.896 17.288 304.992 ;
      RECT 0.048 305.664 17.288 305.76 ;
      RECT 0.048 306.432 17.288 306.528 ;
      RECT 0.048 307.2 17.288 307.296 ;
      RECT 0.048 307.968 17.288 308.064 ;
      RECT 0.048 308.736 17.288 308.832 ;
      RECT 0.048 309.504 17.288 309.6 ;
      RECT 0.048 310.272 17.288 310.368 ;
      RECT 0.048 311.04 17.288 311.136 ;
      RECT 0.048 311.808 17.288 311.904 ;
      RECT 0.048 312.576 17.288 312.672 ;
      RECT 0.048 313.344 17.288 313.44 ;
      RECT 0.048 314.112 17.288 314.208 ;
      RECT 0.048 314.88 17.288 314.976 ;
      RECT 0.048 315.648 17.288 315.744 ;
      RECT 0.048 316.416 17.288 316.512 ;
      RECT 0.048 317.184 17.288 317.28 ;
      RECT 0.048 317.952 17.288 318.048 ;
      RECT 0.048 318.72 17.288 318.816 ;
      RECT 0.048 319.488 17.288 319.584 ;
      RECT 0.048 320.256 17.288 320.352 ;
      RECT 0.048 321.024 17.288 321.12 ;
      RECT 0.048 321.792 17.288 321.888 ;
      RECT 0.048 322.56 17.288 322.656 ;
      RECT 0.048 323.328 17.288 323.424 ;
      RECT 0.048 324.096 17.288 324.192 ;
      RECT 0.048 324.864 17.288 324.96 ;
      RECT 0.048 325.632 17.288 325.728 ;
      RECT 0.048 326.4 17.288 326.496 ;
      RECT 0.048 327.168 17.288 327.264 ;
      RECT 0.048 327.936 17.288 328.032 ;
      RECT 0.048 328.704 17.288 328.8 ;
      RECT 0.048 329.472 17.288 329.568 ;
      RECT 0.048 330.24 17.288 330.336 ;
      RECT 0.048 331.008 17.288 331.104 ;
      RECT 0.048 331.776 17.288 331.872 ;
      RECT 0.048 332.544 17.288 332.64 ;
      RECT 0.048 333.312 17.288 333.408 ;
      RECT 0.048 334.08 17.288 334.176 ;
      RECT 0.048 334.848 17.288 334.944 ;
      RECT 0.048 335.616 17.288 335.712 ;
      RECT 0.048 336.384 17.288 336.48 ;
      RECT 0.048 337.152 17.288 337.248 ;
      RECT 0.048 337.92 17.288 338.016 ;
      RECT 0.048 338.688 17.288 338.784 ;
      RECT 0.048 339.456 17.288 339.552 ;
      RECT 0.048 340.224 17.288 340.32 ;
      RECT 0.048 340.992 17.288 341.088 ;
      RECT 0.048 341.76 17.288 341.856 ;
      RECT 0.048 342.528 17.288 342.624 ;
      RECT 0.048 343.296 17.288 343.392 ;
      RECT 0.048 344.064 17.288 344.16 ;
      RECT 0.048 344.832 17.288 344.928 ;
      RECT 0.048 345.6 17.288 345.696 ;
      RECT 0.048 346.368 17.288 346.464 ;
      RECT 0.048 347.136 17.288 347.232 ;
      RECT 0.048 347.904 17.288 348 ;
      RECT 0.048 348.672 17.288 348.768 ;
      RECT 0.048 349.44 17.288 349.536 ;
      RECT 0.048 350.208 17.288 350.304 ;
      RECT 0.048 350.976 17.288 351.072 ;
      RECT 0.048 351.744 17.288 351.84 ;
      RECT 0.048 352.512 17.288 352.608 ;
      RECT 0.048 353.28 17.288 353.376 ;
      RECT 0.048 354.048 17.288 354.144 ;
      RECT 0.048 354.816 17.288 354.912 ;
      RECT 0.048 355.584 17.288 355.68 ;
      RECT 0.048 356.352 17.288 356.448 ;
      RECT 0.048 357.12 17.288 357.216 ;
      RECT 0.048 357.888 17.288 357.984 ;
      RECT 0.048 358.656 17.288 358.752 ;
      RECT 0.048 359.424 17.288 359.52 ;
      RECT 0.048 360.192 17.288 360.288 ;
      RECT 0.048 360.96 17.288 361.056 ;
      RECT 0.048 361.728 17.288 361.824 ;
      RECT 0.048 362.496 17.288 362.592 ;
      RECT 0.048 363.264 17.288 363.36 ;
      RECT 0.048 364.032 17.288 364.128 ;
      RECT 0.048 364.8 17.288 364.896 ;
      RECT 0.048 365.568 17.288 365.664 ;
      RECT 0.048 366.336 17.288 366.432 ;
      RECT 0.048 367.104 17.288 367.2 ;
      RECT 0.048 367.872 17.288 367.968 ;
      RECT 0.048 368.64 17.288 368.736 ;
      RECT 0.048 369.408 17.288 369.504 ;
      RECT 0.048 370.176 17.288 370.272 ;
      RECT 0.048 370.944 17.288 371.04 ;
      RECT 0.048 371.712 17.288 371.808 ;
      RECT 0.048 372.48 17.288 372.576 ;
      RECT 0.048 373.248 17.288 373.344 ;
      RECT 0.048 374.016 17.288 374.112 ;
      RECT 0.048 374.784 17.288 374.88 ;
      RECT 0.048 375.552 17.288 375.648 ;
      RECT 0.048 376.32 17.288 376.416 ;
      RECT 0.048 377.088 17.288 377.184 ;
      RECT 0.048 377.856 17.288 377.952 ;
      RECT 0.048 378.624 17.288 378.72 ;
      RECT 0.048 379.392 17.288 379.488 ;
      RECT 0.048 380.16 17.288 380.256 ;
      RECT 0.048 380.928 17.288 381.024 ;
      RECT 0.048 381.696 17.288 381.792 ;
      RECT 0.048 382.464 17.288 382.56 ;
      RECT 0.048 383.232 17.288 383.328 ;
      RECT 0.048 384 17.288 384.096 ;
      RECT 0.048 384.768 17.288 384.864 ;
      RECT 0.048 385.536 17.288 385.632 ;
      RECT 0.048 386.304 17.288 386.4 ;
      RECT 0.048 387.072 17.288 387.168 ;
      RECT 0.048 387.84 17.288 387.936 ;
      RECT 0.048 388.608 17.288 388.704 ;
      RECT 0.048 389.376 17.288 389.472 ;
      RECT 0.048 390.144 17.288 390.24 ;
      RECT 0.048 390.912 17.288 391.008 ;
      RECT 0.048 391.68 17.288 391.776 ;
      RECT 0.048 392.448 17.288 392.544 ;
      RECT 0.048 393.216 17.288 393.312 ;
      RECT 0.048 393.984 17.288 394.08 ;
      RECT 0.048 394.752 17.288 394.848 ;
      RECT 0.048 395.52 17.288 395.616 ;
      RECT 0.048 396.288 17.288 396.384 ;
      RECT 0.048 397.056 17.288 397.152 ;
      RECT 0.048 397.824 17.288 397.92 ;
      RECT 0.048 398.592 17.288 398.688 ;
      RECT 0.048 399.36 17.288 399.456 ;
      RECT 0.048 400.128 17.288 400.224 ;
      RECT 0.048 400.896 17.288 400.992 ;
      RECT 0.048 401.664 17.288 401.76 ;
      RECT 0.048 402.432 17.288 402.528 ;
      RECT 0.048 403.2 17.288 403.296 ;
      RECT 0.048 403.968 17.288 404.064 ;
      RECT 0.048 404.736 17.288 404.832 ;
      RECT 0.048 405.504 17.288 405.6 ;
      RECT 0.048 406.272 17.288 406.368 ;
      RECT 0.048 407.04 17.288 407.136 ;
      RECT 0.048 407.808 17.288 407.904 ;
      RECT 0.048 408.576 17.288 408.672 ;
      RECT 0.048 409.344 17.288 409.44 ;
      RECT 0.048 410.112 17.288 410.208 ;
      RECT 0.048 410.88 17.288 410.976 ;
      RECT 0.048 411.648 17.288 411.744 ;
      RECT 0.048 412.416 17.288 412.512 ;
      RECT 0.048 413.184 17.288 413.28 ;
      RECT 0.048 413.952 17.288 414.048 ;
      RECT 0.048 414.72 17.288 414.816 ;
      RECT 0.048 415.488 17.288 415.584 ;
      RECT 0.048 416.256 17.288 416.352 ;
      RECT 0.048 417.024 17.288 417.12 ;
      RECT 0.048 417.792 17.288 417.888 ;
      RECT 0.048 418.56 17.288 418.656 ;
      RECT 0.048 419.328 17.288 419.424 ;
      RECT 0.048 420.096 17.288 420.192 ;
      RECT 0.048 420.864 17.288 420.96 ;
      RECT 0.048 421.632 17.288 421.728 ;
      RECT 0.048 422.4 17.288 422.496 ;
      RECT 0.048 423.168 17.288 423.264 ;
      RECT 0.048 423.936 17.288 424.032 ;
      RECT 0.048 424.704 17.288 424.8 ;
      RECT 0.048 425.472 17.288 425.568 ;
      RECT 0.048 426.24 17.288 426.336 ;
      RECT 0.048 427.008 17.288 427.104 ;
      RECT 0.048 427.776 17.288 427.872 ;
      RECT 0.048 428.544 17.288 428.64 ;
      RECT 0.048 429.312 17.288 429.408 ;
      RECT 0.048 430.08 17.288 430.176 ;
      RECT 0.048 430.848 17.288 430.944 ;
      RECT 0.048 431.616 17.288 431.712 ;
      RECT 0.048 432.384 17.288 432.48 ;
      RECT 0.048 433.152 17.288 433.248 ;
      RECT 0.048 433.92 17.288 434.016 ;
      RECT 0.048 434.688 17.288 434.784 ;
      RECT 0.048 435.456 17.288 435.552 ;
      RECT 0.048 436.224 17.288 436.32 ;
      RECT 0.048 436.992 17.288 437.088 ;
      RECT 0.048 437.76 17.288 437.856 ;
      RECT 0.048 438.528 17.288 438.624 ;
      RECT 0.048 439.296 17.288 439.392 ;
      RECT 0.048 440.064 17.288 440.16 ;
      RECT 0.048 440.832 17.288 440.928 ;
      RECT 0.048 441.6 17.288 441.696 ;
      RECT 0.048 442.368 17.288 442.464 ;
      RECT 0.048 443.136 17.288 443.232 ;
      RECT 0.048 443.904 17.288 444 ;
      RECT 0.048 444.672 17.288 444.768 ;
      RECT 0.048 445.44 17.288 445.536 ;
      RECT 0.048 446.208 17.288 446.304 ;
      RECT 0.048 446.976 17.288 447.072 ;
      RECT 0.048 447.744 17.288 447.84 ;
      RECT 0.048 448.512 17.288 448.608 ;
      RECT 0.048 449.28 17.288 449.376 ;
      RECT 0.048 450.048 17.288 450.144 ;
      RECT 0.048 450.816 17.288 450.912 ;
      RECT 0.048 451.584 17.288 451.68 ;
      RECT 0.048 452.352 17.288 452.448 ;
      RECT 0.048 453.12 17.288 453.216 ;
      RECT 0.048 453.888 17.288 453.984 ;
      RECT 0.048 454.656 17.288 454.752 ;
      RECT 0.048 455.424 17.288 455.52 ;
      RECT 0.048 456.192 17.288 456.288 ;
      RECT 0.048 456.96 17.288 457.056 ;
      RECT 0.048 457.728 17.288 457.824 ;
      RECT 0.048 458.496 17.288 458.592 ;
      RECT 0.048 459.264 17.288 459.36 ;
      RECT 0.048 460.032 17.288 460.128 ;
      RECT 0.048 460.8 17.288 460.896 ;
      RECT 0.048 461.568 17.288 461.664 ;
      RECT 0.048 462.336 17.288 462.432 ;
      RECT 0.048 463.104 17.288 463.2 ;
      RECT 0.048 463.872 17.288 463.968 ;
      RECT 0.048 464.64 17.288 464.736 ;
      RECT 0.048 465.408 17.288 465.504 ;
      RECT 0.048 466.176 17.288 466.272 ;
      RECT 0.048 466.944 17.288 467.04 ;
      RECT 0.048 467.712 17.288 467.808 ;
      RECT 0.048 468.48 17.288 468.576 ;
      RECT 0.048 469.248 17.288 469.344 ;
      RECT 0.048 470.016 17.288 470.112 ;
      RECT 0.048 470.784 17.288 470.88 ;
      RECT 0.048 471.552 17.288 471.648 ;
      RECT 0.048 472.32 17.288 472.416 ;
      RECT 0.048 473.088 17.288 473.184 ;
      RECT 0.048 473.856 17.288 473.952 ;
      RECT 0.048 474.624 17.288 474.72 ;
      RECT 0.048 475.392 17.288 475.488 ;
      RECT 0.048 476.16 17.288 476.256 ;
      RECT 0.048 476.928 17.288 477.024 ;
      RECT 0.048 477.696 17.288 477.792 ;
      RECT 0.048 478.464 17.288 478.56 ;
      RECT 0.048 479.232 17.288 479.328 ;
      RECT 0.048 480 17.288 480.096 ;
      RECT 0.048 480.768 17.288 480.864 ;
      RECT 0.048 481.536 17.288 481.632 ;
      RECT 0.048 482.304 17.288 482.4 ;
      RECT 0.048 483.072 17.288 483.168 ;
      RECT 0.048 483.84 17.288 483.936 ;
      RECT 0.048 484.608 17.288 484.704 ;
      RECT 0.048 485.376 17.288 485.472 ;
      RECT 0.048 486.144 17.288 486.24 ;
      RECT 0.048 486.912 17.288 487.008 ;
      RECT 0.048 487.68 17.288 487.776 ;
      RECT 0.048 488.448 17.288 488.544 ;
      RECT 0.048 489.216 17.288 489.312 ;
      RECT 0.048 489.984 17.288 490.08 ;
      RECT 0.048 490.752 17.288 490.848 ;
      RECT 0.048 491.52 17.288 491.616 ;
      RECT 0.048 492.288 17.288 492.384 ;
      RECT 0.048 493.056 17.288 493.152 ;
      RECT 0.048 493.824 17.288 493.92 ;
      RECT 0.048 494.592 17.288 494.688 ;
      RECT 0.048 495.36 17.288 495.456 ;
      RECT 0.048 496.128 17.288 496.224 ;
      RECT 0.048 496.896 17.288 496.992 ;
      RECT 0.048 497.664 17.288 497.76 ;
      RECT 0.048 498.432 17.288 498.528 ;
      RECT 0.048 499.2 17.288 499.296 ;
      RECT 0.048 499.968 17.288 500.064 ;
      RECT 0.048 500.736 17.288 500.832 ;
      RECT 0.048 501.504 17.288 501.6 ;
      RECT 0.048 502.272 17.288 502.368 ;
      RECT 0.048 503.04 17.288 503.136 ;
      RECT 0.048 503.808 17.288 503.904 ;
      RECT 0.048 504.576 17.288 504.672 ;
      RECT 0.048 505.344 17.288 505.44 ;
      RECT 0.048 506.112 17.288 506.208 ;
      RECT 0.048 506.88 17.288 506.976 ;
      RECT 0.048 507.648 17.288 507.744 ;
      RECT 0.048 508.416 17.288 508.512 ;
      RECT 0.048 509.184 17.288 509.28 ;
      RECT 0.048 509.952 17.288 510.048 ;
      RECT 0.048 510.72 17.288 510.816 ;
      RECT 0.048 511.488 17.288 511.584 ;
      RECT 0.048 512.256 17.288 512.352 ;
      RECT 0.048 513.024 17.288 513.12 ;
      RECT 0.048 513.792 17.288 513.888 ;
      RECT 0.048 514.56 17.288 514.656 ;
      RECT 0.048 515.328 17.288 515.424 ;
      RECT 0.048 516.096 17.288 516.192 ;
      RECT 0.048 516.864 17.288 516.96 ;
      RECT 0.048 517.632 17.288 517.728 ;
      RECT 0.048 518.4 17.288 518.496 ;
      RECT 0.048 519.168 17.288 519.264 ;
      RECT 0.048 519.936 17.288 520.032 ;
      RECT 0.048 520.704 17.288 520.8 ;
      RECT 0.048 521.472 17.288 521.568 ;
      RECT 0.048 522.24 17.288 522.336 ;
      RECT 0.048 523.008 17.288 523.104 ;
      RECT 0.048 523.776 17.288 523.872 ;
      RECT 0.048 524.544 17.288 524.64 ;
      RECT 0.048 525.312 17.288 525.408 ;
      RECT 0.048 526.08 17.288 526.176 ;
      RECT 0.048 526.848 17.288 526.944 ;
      RECT 0.048 527.616 17.288 527.712 ;
      RECT 0.048 528.384 17.288 528.48 ;
      RECT 0.048 529.152 17.288 529.248 ;
      RECT 0.048 529.92 17.288 530.016 ;
      RECT 0.048 530.688 17.288 530.784 ;
      RECT 0.048 531.456 17.288 531.552 ;
      RECT 0.048 532.224 17.288 532.32 ;
      RECT 0.048 532.992 17.288 533.088 ;
      RECT 0.048 533.76 17.288 533.856 ;
      RECT 0.048 534.528 17.288 534.624 ;
      RECT 0.048 535.296 17.288 535.392 ;
      RECT 0.048 536.064 17.288 536.16 ;
      RECT 0.048 536.832 17.288 536.928 ;
      RECT 0.048 537.6 17.288 537.696 ;
      RECT 0.048 538.368 17.288 538.464 ;
      RECT 0.048 539.136 17.288 539.232 ;
      RECT 0.048 539.904 17.288 540 ;
      RECT 0.048 540.672 17.288 540.768 ;
      RECT 0.048 541.44 17.288 541.536 ;
      RECT 0.048 542.208 17.288 542.304 ;
      RECT 0.048 542.976 17.288 543.072 ;
      RECT 0.048 543.744 17.288 543.84 ;
      RECT 0.048 544.512 17.288 544.608 ;
      RECT 0.048 545.28 17.288 545.376 ;
      RECT 0.048 546.048 17.288 546.144 ;
      RECT 0.048 546.816 17.288 546.912 ;
      RECT 0.048 547.584 17.288 547.68 ;
      RECT 0.048 548.352 17.288 548.448 ;
      RECT 0.048 549.12 17.288 549.216 ;
      RECT 0.048 549.888 17.288 549.984 ;
      RECT 0.048 550.656 17.288 550.752 ;
      RECT 0.048 551.424 17.288 551.52 ;
      RECT 0.048 552.192 17.288 552.288 ;
      RECT 0.048 552.96 17.288 553.056 ;
      RECT 0.048 553.728 17.288 553.824 ;
      RECT 0.048 554.496 17.288 554.592 ;
      RECT 0.048 555.264 17.288 555.36 ;
      RECT 0.048 556.032 17.288 556.128 ;
      RECT 0.048 556.8 17.288 556.896 ;
      RECT 0.048 557.568 17.288 557.664 ;
      RECT 0.048 558.336 17.288 558.432 ;
      RECT 0.048 559.104 17.288 559.2 ;
      RECT 0.048 559.872 17.288 559.968 ;
      RECT 0.048 560.64 17.288 560.736 ;
      RECT 0.048 561.408 17.288 561.504 ;
      RECT 0.048 562.176 17.288 562.272 ;
      RECT 0.048 562.944 17.288 563.04 ;
      RECT 0.048 563.712 17.288 563.808 ;
      RECT 0.048 564.48 17.288 564.576 ;
      RECT 0.048 565.248 17.288 565.344 ;
      RECT 0.048 566.016 17.288 566.112 ;
      RECT 0.048 566.784 17.288 566.88 ;
      RECT 0.048 567.552 17.288 567.648 ;
      RECT 0.048 568.32 17.288 568.416 ;
      RECT 0.048 569.088 17.288 569.184 ;
      RECT 0.048 569.856 17.288 569.952 ;
      RECT 0.048 570.624 17.288 570.72 ;
      RECT 0.048 571.392 17.288 571.488 ;
      RECT 0.048 572.16 17.288 572.256 ;
      RECT 0.048 572.928 17.288 573.024 ;
      RECT 0.048 573.696 17.288 573.792 ;
      RECT 0.048 574.464 17.288 574.56 ;
      RECT 0.048 575.232 17.288 575.328 ;
      RECT 0.048 576 17.288 576.096 ;
      RECT 0.048 576.768 17.288 576.864 ;
      RECT 0.048 577.536 17.288 577.632 ;
      RECT 0.048 578.304 17.288 578.4 ;
      RECT 0.048 579.072 17.288 579.168 ;
      RECT 0.048 579.84 17.288 579.936 ;
      RECT 0.048 580.608 17.288 580.704 ;
      RECT 0.048 581.376 17.288 581.472 ;
      RECT 0.048 582.144 17.288 582.24 ;
      RECT 0.048 582.912 17.288 583.008 ;
      RECT 0.048 583.68 17.288 583.776 ;
      RECT 0.048 584.448 17.288 584.544 ;
      RECT 0.048 585.216 17.288 585.312 ;
      RECT 0.048 585.984 17.288 586.08 ;
      RECT 0.048 586.752 17.288 586.848 ;
      RECT 0.048 587.52 17.288 587.616 ;
      RECT 0.048 588.288 17.288 588.384 ;
      RECT 0.048 589.056 17.288 589.152 ;
      RECT 0.048 589.824 17.288 589.92 ;
      RECT 0.048 590.592 17.288 590.688 ;
      RECT 0.048 591.36 17.288 591.456 ;
      RECT 0.048 592.128 17.288 592.224 ;
      RECT 0.048 592.896 17.288 592.992 ;
      RECT 0.048 593.664 17.288 593.76 ;
      RECT 0.048 594.432 17.288 594.528 ;
      RECT 0.048 595.2 17.288 595.296 ;
      RECT 0.048 595.968 17.288 596.064 ;
      RECT 0.048 596.736 17.288 596.832 ;
      RECT 0.048 597.504 17.288 597.6 ;
      RECT 0.048 598.272 17.288 598.368 ;
      RECT 0.048 599.04 17.288 599.136 ;
      RECT 0.048 599.808 17.288 599.904 ;
      RECT 0.048 600.576 17.288 600.672 ;
      RECT 0.048 601.344 17.288 601.44 ;
      RECT 0.048 602.112 17.288 602.208 ;
      RECT 0.048 602.88 17.288 602.976 ;
      RECT 0.048 603.648 17.288 603.744 ;
      RECT 0.048 604.416 17.288 604.512 ;
      RECT 0.048 605.184 17.288 605.28 ;
      RECT 0.048 605.952 17.288 606.048 ;
      RECT 0.048 606.72 17.288 606.816 ;
      RECT 0.048 607.488 17.288 607.584 ;
      RECT 0.048 608.256 17.288 608.352 ;
      RECT 0.048 609.024 17.288 609.12 ;
      RECT 0.048 609.792 17.288 609.888 ;
      RECT 0.048 610.56 17.288 610.656 ;
      RECT 0.048 611.328 17.288 611.424 ;
      RECT 0.048 612.096 17.288 612.192 ;
      RECT 0.048 612.864 17.288 612.96 ;
      RECT 0.048 613.632 17.288 613.728 ;
      RECT 0.048 614.4 17.288 614.496 ;
      RECT 0.048 615.168 17.288 615.264 ;
      RECT 0.048 615.936 17.288 616.032 ;
      RECT 0.048 616.704 17.288 616.8 ;
      RECT 0.048 617.472 17.288 617.568 ;
      RECT 0.048 618.24 17.288 618.336 ;
      RECT 0.048 619.008 17.288 619.104 ;
      RECT 0.048 619.776 17.288 619.872 ;
      RECT 0.048 620.544 17.288 620.64 ;
      RECT 0.048 621.312 17.288 621.408 ;
      RECT 0.048 622.08 17.288 622.176 ;
      RECT 0.048 622.848 17.288 622.944 ;
      RECT 0.048 623.616 17.288 623.712 ;
      RECT 0.048 624.384 17.288 624.48 ;
      RECT 0.048 625.152 17.288 625.248 ;
      RECT 0.048 625.92 17.288 626.016 ;
      RECT 0.048 626.688 17.288 626.784 ;
      RECT 0.048 627.456 17.288 627.552 ;
      RECT 0.048 628.224 17.288 628.32 ;
      RECT 0.048 628.992 17.288 629.088 ;
      RECT 0.048 629.76 17.288 629.856 ;
      RECT 0.048 630.528 17.288 630.624 ;
      RECT 0.048 631.296 17.288 631.392 ;
      RECT 0.048 632.064 17.288 632.16 ;
      RECT 0.048 632.832 17.288 632.928 ;
      RECT 0.048 633.6 17.288 633.696 ;
      RECT 0.048 634.368 17.288 634.464 ;
      RECT 0.048 635.136 17.288 635.232 ;
      RECT 0.048 635.904 17.288 636 ;
      RECT 0.048 636.672 17.288 636.768 ;
      RECT 0.048 637.44 17.288 637.536 ;
      RECT 0.048 638.208 17.288 638.304 ;
      RECT 0.048 638.976 17.288 639.072 ;
      RECT 0.048 639.744 17.288 639.84 ;
      RECT 0.048 640.512 17.288 640.608 ;
      RECT 0.048 641.28 17.288 641.376 ;
      RECT 0.048 642.048 17.288 642.144 ;
      RECT 0.048 642.816 17.288 642.912 ;
      RECT 0.048 643.584 17.288 643.68 ;
      RECT 0.048 644.352 17.288 644.448 ;
      RECT 0.048 645.12 17.288 645.216 ;
      RECT 0.048 645.888 17.288 645.984 ;
      RECT 0.048 646.656 17.288 646.752 ;
      RECT 0.048 647.424 17.288 647.52 ;
      RECT 0.048 648.192 17.288 648.288 ;
      RECT 0.048 648.96 17.288 649.056 ;
      RECT 0.048 649.728 17.288 649.824 ;
      RECT 0.048 650.496 17.288 650.592 ;
      RECT 0.048 651.264 17.288 651.36 ;
      RECT 0.048 652.032 17.288 652.128 ;
      RECT 0.048 652.8 17.288 652.896 ;
      RECT 0.048 653.568 17.288 653.664 ;
      RECT 0.048 654.336 17.288 654.432 ;
      RECT 0.048 655.104 17.288 655.2 ;
      RECT 0.048 655.872 17.288 655.968 ;
      RECT 0.048 656.64 17.288 656.736 ;
      RECT 0.048 657.408 17.288 657.504 ;
      RECT 0.048 658.176 17.288 658.272 ;
      RECT 0.048 658.944 17.288 659.04 ;
      RECT 0.048 659.712 17.288 659.808 ;
      RECT 0.048 660.48 17.288 660.576 ;
      RECT 0.048 661.248 17.288 661.344 ;
      RECT 0.048 662.016 17.288 662.112 ;
      RECT 0.048 662.784 17.288 662.88 ;
      RECT 0.048 663.552 17.288 663.648 ;
      RECT 0.048 664.32 17.288 664.416 ;
      RECT 0.048 665.088 17.288 665.184 ;
      RECT 0.048 665.856 17.288 665.952 ;
      RECT 0.048 666.624 17.288 666.72 ;
      RECT 0.048 667.392 17.288 667.488 ;
      RECT 0.048 668.16 17.288 668.256 ;
      RECT 0.048 668.928 17.288 669.024 ;
      RECT 0.048 669.696 17.288 669.792 ;
      RECT 0.048 670.464 17.288 670.56 ;
      RECT 0.048 671.232 17.288 671.328 ;
      RECT 0.048 672 17.288 672.096 ;
      RECT 0.048 672.768 17.288 672.864 ;
      RECT 0.048 673.536 17.288 673.632 ;
      RECT 0.048 674.304 17.288 674.4 ;
      RECT 0.048 675.072 17.288 675.168 ;
      RECT 0.048 675.84 17.288 675.936 ;
      RECT 0.048 676.608 17.288 676.704 ;
      RECT 0.048 677.376 17.288 677.472 ;
      RECT 0.048 678.144 17.288 678.24 ;
      RECT 0.048 678.912 17.288 679.008 ;
      RECT 0.048 679.68 17.288 679.776 ;
      RECT 0.048 680.448 17.288 680.544 ;
      RECT 0.048 681.216 17.288 681.312 ;
      RECT 0.048 681.984 17.288 682.08 ;
      RECT 0.048 682.752 17.288 682.848 ;
      RECT 0.048 683.52 17.288 683.616 ;
      RECT 0.048 684.288 17.288 684.384 ;
      RECT 0.048 685.056 17.288 685.152 ;
      RECT 0.048 685.824 17.288 685.92 ;
      RECT 0.048 686.592 17.288 686.688 ;
      RECT 0.048 687.36 17.288 687.456 ;
      RECT 0.048 688.128 17.288 688.224 ;
      RECT 0.048 688.896 17.288 688.992 ;
      RECT 0.048 689.664 17.288 689.76 ;
      RECT 0.048 690.432 17.288 690.528 ;
      RECT 0.048 691.2 17.288 691.296 ;
      RECT 0.048 691.968 17.288 692.064 ;
      RECT 0.048 692.736 17.288 692.832 ;
      RECT 0.048 693.504 17.288 693.6 ;
      RECT 0.048 694.272 17.288 694.368 ;
      RECT 0.048 695.04 17.288 695.136 ;
      RECT 0.048 695.808 17.288 695.904 ;
    END
  END VSS
  PIN VDD
    DIRECTION INOUT ;
    USE POWER ;
    PORT
      LAYER M4_m ;
      RECT 0.048 0.384 17.288 0.48 ;
      RECT 0.048 1.152 17.288 1.248 ;
      RECT 0.048 1.92 17.288 2.016 ;
      RECT 0.048 2.688 17.288 2.784 ;
      RECT 0.048 3.456 17.288 3.552 ;
      RECT 0.048 4.224 17.288 4.32 ;
      RECT 0.048 4.992 17.288 5.088 ;
      RECT 0.048 5.76 17.288 5.856 ;
      RECT 0.048 6.528 17.288 6.624 ;
      RECT 0.048 7.296 17.288 7.392 ;
      RECT 0.048 8.064 17.288 8.16 ;
      RECT 0.048 8.832 17.288 8.928 ;
      RECT 0.048 9.6 17.288 9.696 ;
      RECT 0.048 10.368 17.288 10.464 ;
      RECT 0.048 11.136 17.288 11.232 ;
      RECT 0.048 11.904 17.288 12 ;
      RECT 0.048 12.672 17.288 12.768 ;
      RECT 0.048 13.44 17.288 13.536 ;
      RECT 0.048 14.208 17.288 14.304 ;
      RECT 0.048 14.976 17.288 15.072 ;
      RECT 0.048 15.744 17.288 15.84 ;
      RECT 0.048 16.512 17.288 16.608 ;
      RECT 0.048 17.28 17.288 17.376 ;
      RECT 0.048 18.048 17.288 18.144 ;
      RECT 0.048 18.816 17.288 18.912 ;
      RECT 0.048 19.584 17.288 19.68 ;
      RECT 0.048 20.352 17.288 20.448 ;
      RECT 0.048 21.12 17.288 21.216 ;
      RECT 0.048 21.888 17.288 21.984 ;
      RECT 0.048 22.656 17.288 22.752 ;
      RECT 0.048 23.424 17.288 23.52 ;
      RECT 0.048 24.192 17.288 24.288 ;
      RECT 0.048 24.96 17.288 25.056 ;
      RECT 0.048 25.728 17.288 25.824 ;
      RECT 0.048 26.496 17.288 26.592 ;
      RECT 0.048 27.264 17.288 27.36 ;
      RECT 0.048 28.032 17.288 28.128 ;
      RECT 0.048 28.8 17.288 28.896 ;
      RECT 0.048 29.568 17.288 29.664 ;
      RECT 0.048 30.336 17.288 30.432 ;
      RECT 0.048 31.104 17.288 31.2 ;
      RECT 0.048 31.872 17.288 31.968 ;
      RECT 0.048 32.64 17.288 32.736 ;
      RECT 0.048 33.408 17.288 33.504 ;
      RECT 0.048 34.176 17.288 34.272 ;
      RECT 0.048 34.944 17.288 35.04 ;
      RECT 0.048 35.712 17.288 35.808 ;
      RECT 0.048 36.48 17.288 36.576 ;
      RECT 0.048 37.248 17.288 37.344 ;
      RECT 0.048 38.016 17.288 38.112 ;
      RECT 0.048 38.784 17.288 38.88 ;
      RECT 0.048 39.552 17.288 39.648 ;
      RECT 0.048 40.32 17.288 40.416 ;
      RECT 0.048 41.088 17.288 41.184 ;
      RECT 0.048 41.856 17.288 41.952 ;
      RECT 0.048 42.624 17.288 42.72 ;
      RECT 0.048 43.392 17.288 43.488 ;
      RECT 0.048 44.16 17.288 44.256 ;
      RECT 0.048 44.928 17.288 45.024 ;
      RECT 0.048 45.696 17.288 45.792 ;
      RECT 0.048 46.464 17.288 46.56 ;
      RECT 0.048 47.232 17.288 47.328 ;
      RECT 0.048 48 17.288 48.096 ;
      RECT 0.048 48.768 17.288 48.864 ;
      RECT 0.048 49.536 17.288 49.632 ;
      RECT 0.048 50.304 17.288 50.4 ;
      RECT 0.048 51.072 17.288 51.168 ;
      RECT 0.048 51.84 17.288 51.936 ;
      RECT 0.048 52.608 17.288 52.704 ;
      RECT 0.048 53.376 17.288 53.472 ;
      RECT 0.048 54.144 17.288 54.24 ;
      RECT 0.048 54.912 17.288 55.008 ;
      RECT 0.048 55.68 17.288 55.776 ;
      RECT 0.048 56.448 17.288 56.544 ;
      RECT 0.048 57.216 17.288 57.312 ;
      RECT 0.048 57.984 17.288 58.08 ;
      RECT 0.048 58.752 17.288 58.848 ;
      RECT 0.048 59.52 17.288 59.616 ;
      RECT 0.048 60.288 17.288 60.384 ;
      RECT 0.048 61.056 17.288 61.152 ;
      RECT 0.048 61.824 17.288 61.92 ;
      RECT 0.048 62.592 17.288 62.688 ;
      RECT 0.048 63.36 17.288 63.456 ;
      RECT 0.048 64.128 17.288 64.224 ;
      RECT 0.048 64.896 17.288 64.992 ;
      RECT 0.048 65.664 17.288 65.76 ;
      RECT 0.048 66.432 17.288 66.528 ;
      RECT 0.048 67.2 17.288 67.296 ;
      RECT 0.048 67.968 17.288 68.064 ;
      RECT 0.048 68.736 17.288 68.832 ;
      RECT 0.048 69.504 17.288 69.6 ;
      RECT 0.048 70.272 17.288 70.368 ;
      RECT 0.048 71.04 17.288 71.136 ;
      RECT 0.048 71.808 17.288 71.904 ;
      RECT 0.048 72.576 17.288 72.672 ;
      RECT 0.048 73.344 17.288 73.44 ;
      RECT 0.048 74.112 17.288 74.208 ;
      RECT 0.048 74.88 17.288 74.976 ;
      RECT 0.048 75.648 17.288 75.744 ;
      RECT 0.048 76.416 17.288 76.512 ;
      RECT 0.048 77.184 17.288 77.28 ;
      RECT 0.048 77.952 17.288 78.048 ;
      RECT 0.048 78.72 17.288 78.816 ;
      RECT 0.048 79.488 17.288 79.584 ;
      RECT 0.048 80.256 17.288 80.352 ;
      RECT 0.048 81.024 17.288 81.12 ;
      RECT 0.048 81.792 17.288 81.888 ;
      RECT 0.048 82.56 17.288 82.656 ;
      RECT 0.048 83.328 17.288 83.424 ;
      RECT 0.048 84.096 17.288 84.192 ;
      RECT 0.048 84.864 17.288 84.96 ;
      RECT 0.048 85.632 17.288 85.728 ;
      RECT 0.048 86.4 17.288 86.496 ;
      RECT 0.048 87.168 17.288 87.264 ;
      RECT 0.048 87.936 17.288 88.032 ;
      RECT 0.048 88.704 17.288 88.8 ;
      RECT 0.048 89.472 17.288 89.568 ;
      RECT 0.048 90.24 17.288 90.336 ;
      RECT 0.048 91.008 17.288 91.104 ;
      RECT 0.048 91.776 17.288 91.872 ;
      RECT 0.048 92.544 17.288 92.64 ;
      RECT 0.048 93.312 17.288 93.408 ;
      RECT 0.048 94.08 17.288 94.176 ;
      RECT 0.048 94.848 17.288 94.944 ;
      RECT 0.048 95.616 17.288 95.712 ;
      RECT 0.048 96.384 17.288 96.48 ;
      RECT 0.048 97.152 17.288 97.248 ;
      RECT 0.048 97.92 17.288 98.016 ;
      RECT 0.048 98.688 17.288 98.784 ;
      RECT 0.048 99.456 17.288 99.552 ;
      RECT 0.048 100.224 17.288 100.32 ;
      RECT 0.048 100.992 17.288 101.088 ;
      RECT 0.048 101.76 17.288 101.856 ;
      RECT 0.048 102.528 17.288 102.624 ;
      RECT 0.048 103.296 17.288 103.392 ;
      RECT 0.048 104.064 17.288 104.16 ;
      RECT 0.048 104.832 17.288 104.928 ;
      RECT 0.048 105.6 17.288 105.696 ;
      RECT 0.048 106.368 17.288 106.464 ;
      RECT 0.048 107.136 17.288 107.232 ;
      RECT 0.048 107.904 17.288 108 ;
      RECT 0.048 108.672 17.288 108.768 ;
      RECT 0.048 109.44 17.288 109.536 ;
      RECT 0.048 110.208 17.288 110.304 ;
      RECT 0.048 110.976 17.288 111.072 ;
      RECT 0.048 111.744 17.288 111.84 ;
      RECT 0.048 112.512 17.288 112.608 ;
      RECT 0.048 113.28 17.288 113.376 ;
      RECT 0.048 114.048 17.288 114.144 ;
      RECT 0.048 114.816 17.288 114.912 ;
      RECT 0.048 115.584 17.288 115.68 ;
      RECT 0.048 116.352 17.288 116.448 ;
      RECT 0.048 117.12 17.288 117.216 ;
      RECT 0.048 117.888 17.288 117.984 ;
      RECT 0.048 118.656 17.288 118.752 ;
      RECT 0.048 119.424 17.288 119.52 ;
      RECT 0.048 120.192 17.288 120.288 ;
      RECT 0.048 120.96 17.288 121.056 ;
      RECT 0.048 121.728 17.288 121.824 ;
      RECT 0.048 122.496 17.288 122.592 ;
      RECT 0.048 123.264 17.288 123.36 ;
      RECT 0.048 124.032 17.288 124.128 ;
      RECT 0.048 124.8 17.288 124.896 ;
      RECT 0.048 125.568 17.288 125.664 ;
      RECT 0.048 126.336 17.288 126.432 ;
      RECT 0.048 127.104 17.288 127.2 ;
      RECT 0.048 127.872 17.288 127.968 ;
      RECT 0.048 128.64 17.288 128.736 ;
      RECT 0.048 129.408 17.288 129.504 ;
      RECT 0.048 130.176 17.288 130.272 ;
      RECT 0.048 130.944 17.288 131.04 ;
      RECT 0.048 131.712 17.288 131.808 ;
      RECT 0.048 132.48 17.288 132.576 ;
      RECT 0.048 133.248 17.288 133.344 ;
      RECT 0.048 134.016 17.288 134.112 ;
      RECT 0.048 134.784 17.288 134.88 ;
      RECT 0.048 135.552 17.288 135.648 ;
      RECT 0.048 136.32 17.288 136.416 ;
      RECT 0.048 137.088 17.288 137.184 ;
      RECT 0.048 137.856 17.288 137.952 ;
      RECT 0.048 138.624 17.288 138.72 ;
      RECT 0.048 139.392 17.288 139.488 ;
      RECT 0.048 140.16 17.288 140.256 ;
      RECT 0.048 140.928 17.288 141.024 ;
      RECT 0.048 141.696 17.288 141.792 ;
      RECT 0.048 142.464 17.288 142.56 ;
      RECT 0.048 143.232 17.288 143.328 ;
      RECT 0.048 144 17.288 144.096 ;
      RECT 0.048 144.768 17.288 144.864 ;
      RECT 0.048 145.536 17.288 145.632 ;
      RECT 0.048 146.304 17.288 146.4 ;
      RECT 0.048 147.072 17.288 147.168 ;
      RECT 0.048 147.84 17.288 147.936 ;
      RECT 0.048 148.608 17.288 148.704 ;
      RECT 0.048 149.376 17.288 149.472 ;
      RECT 0.048 150.144 17.288 150.24 ;
      RECT 0.048 150.912 17.288 151.008 ;
      RECT 0.048 151.68 17.288 151.776 ;
      RECT 0.048 152.448 17.288 152.544 ;
      RECT 0.048 153.216 17.288 153.312 ;
      RECT 0.048 153.984 17.288 154.08 ;
      RECT 0.048 154.752 17.288 154.848 ;
      RECT 0.048 155.52 17.288 155.616 ;
      RECT 0.048 156.288 17.288 156.384 ;
      RECT 0.048 157.056 17.288 157.152 ;
      RECT 0.048 157.824 17.288 157.92 ;
      RECT 0.048 158.592 17.288 158.688 ;
      RECT 0.048 159.36 17.288 159.456 ;
      RECT 0.048 160.128 17.288 160.224 ;
      RECT 0.048 160.896 17.288 160.992 ;
      RECT 0.048 161.664 17.288 161.76 ;
      RECT 0.048 162.432 17.288 162.528 ;
      RECT 0.048 163.2 17.288 163.296 ;
      RECT 0.048 163.968 17.288 164.064 ;
      RECT 0.048 164.736 17.288 164.832 ;
      RECT 0.048 165.504 17.288 165.6 ;
      RECT 0.048 166.272 17.288 166.368 ;
      RECT 0.048 167.04 17.288 167.136 ;
      RECT 0.048 167.808 17.288 167.904 ;
      RECT 0.048 168.576 17.288 168.672 ;
      RECT 0.048 169.344 17.288 169.44 ;
      RECT 0.048 170.112 17.288 170.208 ;
      RECT 0.048 170.88 17.288 170.976 ;
      RECT 0.048 171.648 17.288 171.744 ;
      RECT 0.048 172.416 17.288 172.512 ;
      RECT 0.048 173.184 17.288 173.28 ;
      RECT 0.048 173.952 17.288 174.048 ;
      RECT 0.048 174.72 17.288 174.816 ;
      RECT 0.048 175.488 17.288 175.584 ;
      RECT 0.048 176.256 17.288 176.352 ;
      RECT 0.048 177.024 17.288 177.12 ;
      RECT 0.048 177.792 17.288 177.888 ;
      RECT 0.048 178.56 17.288 178.656 ;
      RECT 0.048 179.328 17.288 179.424 ;
      RECT 0.048 180.096 17.288 180.192 ;
      RECT 0.048 180.864 17.288 180.96 ;
      RECT 0.048 181.632 17.288 181.728 ;
      RECT 0.048 182.4 17.288 182.496 ;
      RECT 0.048 183.168 17.288 183.264 ;
      RECT 0.048 183.936 17.288 184.032 ;
      RECT 0.048 184.704 17.288 184.8 ;
      RECT 0.048 185.472 17.288 185.568 ;
      RECT 0.048 186.24 17.288 186.336 ;
      RECT 0.048 187.008 17.288 187.104 ;
      RECT 0.048 187.776 17.288 187.872 ;
      RECT 0.048 188.544 17.288 188.64 ;
      RECT 0.048 189.312 17.288 189.408 ;
      RECT 0.048 190.08 17.288 190.176 ;
      RECT 0.048 190.848 17.288 190.944 ;
      RECT 0.048 191.616 17.288 191.712 ;
      RECT 0.048 192.384 17.288 192.48 ;
      RECT 0.048 193.152 17.288 193.248 ;
      RECT 0.048 193.92 17.288 194.016 ;
      RECT 0.048 194.688 17.288 194.784 ;
      RECT 0.048 195.456 17.288 195.552 ;
      RECT 0.048 196.224 17.288 196.32 ;
      RECT 0.048 196.992 17.288 197.088 ;
      RECT 0.048 197.76 17.288 197.856 ;
      RECT 0.048 198.528 17.288 198.624 ;
      RECT 0.048 199.296 17.288 199.392 ;
      RECT 0.048 200.064 17.288 200.16 ;
      RECT 0.048 200.832 17.288 200.928 ;
      RECT 0.048 201.6 17.288 201.696 ;
      RECT 0.048 202.368 17.288 202.464 ;
      RECT 0.048 203.136 17.288 203.232 ;
      RECT 0.048 203.904 17.288 204 ;
      RECT 0.048 204.672 17.288 204.768 ;
      RECT 0.048 205.44 17.288 205.536 ;
      RECT 0.048 206.208 17.288 206.304 ;
      RECT 0.048 206.976 17.288 207.072 ;
      RECT 0.048 207.744 17.288 207.84 ;
      RECT 0.048 208.512 17.288 208.608 ;
      RECT 0.048 209.28 17.288 209.376 ;
      RECT 0.048 210.048 17.288 210.144 ;
      RECT 0.048 210.816 17.288 210.912 ;
      RECT 0.048 211.584 17.288 211.68 ;
      RECT 0.048 212.352 17.288 212.448 ;
      RECT 0.048 213.12 17.288 213.216 ;
      RECT 0.048 213.888 17.288 213.984 ;
      RECT 0.048 214.656 17.288 214.752 ;
      RECT 0.048 215.424 17.288 215.52 ;
      RECT 0.048 216.192 17.288 216.288 ;
      RECT 0.048 216.96 17.288 217.056 ;
      RECT 0.048 217.728 17.288 217.824 ;
      RECT 0.048 218.496 17.288 218.592 ;
      RECT 0.048 219.264 17.288 219.36 ;
      RECT 0.048 220.032 17.288 220.128 ;
      RECT 0.048 220.8 17.288 220.896 ;
      RECT 0.048 221.568 17.288 221.664 ;
      RECT 0.048 222.336 17.288 222.432 ;
      RECT 0.048 223.104 17.288 223.2 ;
      RECT 0.048 223.872 17.288 223.968 ;
      RECT 0.048 224.64 17.288 224.736 ;
      RECT 0.048 225.408 17.288 225.504 ;
      RECT 0.048 226.176 17.288 226.272 ;
      RECT 0.048 226.944 17.288 227.04 ;
      RECT 0.048 227.712 17.288 227.808 ;
      RECT 0.048 228.48 17.288 228.576 ;
      RECT 0.048 229.248 17.288 229.344 ;
      RECT 0.048 230.016 17.288 230.112 ;
      RECT 0.048 230.784 17.288 230.88 ;
      RECT 0.048 231.552 17.288 231.648 ;
      RECT 0.048 232.32 17.288 232.416 ;
      RECT 0.048 233.088 17.288 233.184 ;
      RECT 0.048 233.856 17.288 233.952 ;
      RECT 0.048 234.624 17.288 234.72 ;
      RECT 0.048 235.392 17.288 235.488 ;
      RECT 0.048 236.16 17.288 236.256 ;
      RECT 0.048 236.928 17.288 237.024 ;
      RECT 0.048 237.696 17.288 237.792 ;
      RECT 0.048 238.464 17.288 238.56 ;
      RECT 0.048 239.232 17.288 239.328 ;
      RECT 0.048 240 17.288 240.096 ;
      RECT 0.048 240.768 17.288 240.864 ;
      RECT 0.048 241.536 17.288 241.632 ;
      RECT 0.048 242.304 17.288 242.4 ;
      RECT 0.048 243.072 17.288 243.168 ;
      RECT 0.048 243.84 17.288 243.936 ;
      RECT 0.048 244.608 17.288 244.704 ;
      RECT 0.048 245.376 17.288 245.472 ;
      RECT 0.048 246.144 17.288 246.24 ;
      RECT 0.048 246.912 17.288 247.008 ;
      RECT 0.048 247.68 17.288 247.776 ;
      RECT 0.048 248.448 17.288 248.544 ;
      RECT 0.048 249.216 17.288 249.312 ;
      RECT 0.048 249.984 17.288 250.08 ;
      RECT 0.048 250.752 17.288 250.848 ;
      RECT 0.048 251.52 17.288 251.616 ;
      RECT 0.048 252.288 17.288 252.384 ;
      RECT 0.048 253.056 17.288 253.152 ;
      RECT 0.048 253.824 17.288 253.92 ;
      RECT 0.048 254.592 17.288 254.688 ;
      RECT 0.048 255.36 17.288 255.456 ;
      RECT 0.048 256.128 17.288 256.224 ;
      RECT 0.048 256.896 17.288 256.992 ;
      RECT 0.048 257.664 17.288 257.76 ;
      RECT 0.048 258.432 17.288 258.528 ;
      RECT 0.048 259.2 17.288 259.296 ;
      RECT 0.048 259.968 17.288 260.064 ;
      RECT 0.048 260.736 17.288 260.832 ;
      RECT 0.048 261.504 17.288 261.6 ;
      RECT 0.048 262.272 17.288 262.368 ;
      RECT 0.048 263.04 17.288 263.136 ;
      RECT 0.048 263.808 17.288 263.904 ;
      RECT 0.048 264.576 17.288 264.672 ;
      RECT 0.048 265.344 17.288 265.44 ;
      RECT 0.048 266.112 17.288 266.208 ;
      RECT 0.048 266.88 17.288 266.976 ;
      RECT 0.048 267.648 17.288 267.744 ;
      RECT 0.048 268.416 17.288 268.512 ;
      RECT 0.048 269.184 17.288 269.28 ;
      RECT 0.048 269.952 17.288 270.048 ;
      RECT 0.048 270.72 17.288 270.816 ;
      RECT 0.048 271.488 17.288 271.584 ;
      RECT 0.048 272.256 17.288 272.352 ;
      RECT 0.048 273.024 17.288 273.12 ;
      RECT 0.048 273.792 17.288 273.888 ;
      RECT 0.048 274.56 17.288 274.656 ;
      RECT 0.048 275.328 17.288 275.424 ;
      RECT 0.048 276.096 17.288 276.192 ;
      RECT 0.048 276.864 17.288 276.96 ;
      RECT 0.048 277.632 17.288 277.728 ;
      RECT 0.048 278.4 17.288 278.496 ;
      RECT 0.048 279.168 17.288 279.264 ;
      RECT 0.048 279.936 17.288 280.032 ;
      RECT 0.048 280.704 17.288 280.8 ;
      RECT 0.048 281.472 17.288 281.568 ;
      RECT 0.048 282.24 17.288 282.336 ;
      RECT 0.048 283.008 17.288 283.104 ;
      RECT 0.048 283.776 17.288 283.872 ;
      RECT 0.048 284.544 17.288 284.64 ;
      RECT 0.048 285.312 17.288 285.408 ;
      RECT 0.048 286.08 17.288 286.176 ;
      RECT 0.048 286.848 17.288 286.944 ;
      RECT 0.048 287.616 17.288 287.712 ;
      RECT 0.048 288.384 17.288 288.48 ;
      RECT 0.048 289.152 17.288 289.248 ;
      RECT 0.048 289.92 17.288 290.016 ;
      RECT 0.048 290.688 17.288 290.784 ;
      RECT 0.048 291.456 17.288 291.552 ;
      RECT 0.048 292.224 17.288 292.32 ;
      RECT 0.048 292.992 17.288 293.088 ;
      RECT 0.048 293.76 17.288 293.856 ;
      RECT 0.048 294.528 17.288 294.624 ;
      RECT 0.048 295.296 17.288 295.392 ;
      RECT 0.048 296.064 17.288 296.16 ;
      RECT 0.048 296.832 17.288 296.928 ;
      RECT 0.048 297.6 17.288 297.696 ;
      RECT 0.048 298.368 17.288 298.464 ;
      RECT 0.048 299.136 17.288 299.232 ;
      RECT 0.048 299.904 17.288 300 ;
      RECT 0.048 300.672 17.288 300.768 ;
      RECT 0.048 301.44 17.288 301.536 ;
      RECT 0.048 302.208 17.288 302.304 ;
      RECT 0.048 302.976 17.288 303.072 ;
      RECT 0.048 303.744 17.288 303.84 ;
      RECT 0.048 304.512 17.288 304.608 ;
      RECT 0.048 305.28 17.288 305.376 ;
      RECT 0.048 306.048 17.288 306.144 ;
      RECT 0.048 306.816 17.288 306.912 ;
      RECT 0.048 307.584 17.288 307.68 ;
      RECT 0.048 308.352 17.288 308.448 ;
      RECT 0.048 309.12 17.288 309.216 ;
      RECT 0.048 309.888 17.288 309.984 ;
      RECT 0.048 310.656 17.288 310.752 ;
      RECT 0.048 311.424 17.288 311.52 ;
      RECT 0.048 312.192 17.288 312.288 ;
      RECT 0.048 312.96 17.288 313.056 ;
      RECT 0.048 313.728 17.288 313.824 ;
      RECT 0.048 314.496 17.288 314.592 ;
      RECT 0.048 315.264 17.288 315.36 ;
      RECT 0.048 316.032 17.288 316.128 ;
      RECT 0.048 316.8 17.288 316.896 ;
      RECT 0.048 317.568 17.288 317.664 ;
      RECT 0.048 318.336 17.288 318.432 ;
      RECT 0.048 319.104 17.288 319.2 ;
      RECT 0.048 319.872 17.288 319.968 ;
      RECT 0.048 320.64 17.288 320.736 ;
      RECT 0.048 321.408 17.288 321.504 ;
      RECT 0.048 322.176 17.288 322.272 ;
      RECT 0.048 322.944 17.288 323.04 ;
      RECT 0.048 323.712 17.288 323.808 ;
      RECT 0.048 324.48 17.288 324.576 ;
      RECT 0.048 325.248 17.288 325.344 ;
      RECT 0.048 326.016 17.288 326.112 ;
      RECT 0.048 326.784 17.288 326.88 ;
      RECT 0.048 327.552 17.288 327.648 ;
      RECT 0.048 328.32 17.288 328.416 ;
      RECT 0.048 329.088 17.288 329.184 ;
      RECT 0.048 329.856 17.288 329.952 ;
      RECT 0.048 330.624 17.288 330.72 ;
      RECT 0.048 331.392 17.288 331.488 ;
      RECT 0.048 332.16 17.288 332.256 ;
      RECT 0.048 332.928 17.288 333.024 ;
      RECT 0.048 333.696 17.288 333.792 ;
      RECT 0.048 334.464 17.288 334.56 ;
      RECT 0.048 335.232 17.288 335.328 ;
      RECT 0.048 336 17.288 336.096 ;
      RECT 0.048 336.768 17.288 336.864 ;
      RECT 0.048 337.536 17.288 337.632 ;
      RECT 0.048 338.304 17.288 338.4 ;
      RECT 0.048 339.072 17.288 339.168 ;
      RECT 0.048 339.84 17.288 339.936 ;
      RECT 0.048 340.608 17.288 340.704 ;
      RECT 0.048 341.376 17.288 341.472 ;
      RECT 0.048 342.144 17.288 342.24 ;
      RECT 0.048 342.912 17.288 343.008 ;
      RECT 0.048 343.68 17.288 343.776 ;
      RECT 0.048 344.448 17.288 344.544 ;
      RECT 0.048 345.216 17.288 345.312 ;
      RECT 0.048 345.984 17.288 346.08 ;
      RECT 0.048 346.752 17.288 346.848 ;
      RECT 0.048 347.52 17.288 347.616 ;
      RECT 0.048 348.288 17.288 348.384 ;
      RECT 0.048 349.056 17.288 349.152 ;
      RECT 0.048 349.824 17.288 349.92 ;
      RECT 0.048 350.592 17.288 350.688 ;
      RECT 0.048 351.36 17.288 351.456 ;
      RECT 0.048 352.128 17.288 352.224 ;
      RECT 0.048 352.896 17.288 352.992 ;
      RECT 0.048 353.664 17.288 353.76 ;
      RECT 0.048 354.432 17.288 354.528 ;
      RECT 0.048 355.2 17.288 355.296 ;
      RECT 0.048 355.968 17.288 356.064 ;
      RECT 0.048 356.736 17.288 356.832 ;
      RECT 0.048 357.504 17.288 357.6 ;
      RECT 0.048 358.272 17.288 358.368 ;
      RECT 0.048 359.04 17.288 359.136 ;
      RECT 0.048 359.808 17.288 359.904 ;
      RECT 0.048 360.576 17.288 360.672 ;
      RECT 0.048 361.344 17.288 361.44 ;
      RECT 0.048 362.112 17.288 362.208 ;
      RECT 0.048 362.88 17.288 362.976 ;
      RECT 0.048 363.648 17.288 363.744 ;
      RECT 0.048 364.416 17.288 364.512 ;
      RECT 0.048 365.184 17.288 365.28 ;
      RECT 0.048 365.952 17.288 366.048 ;
      RECT 0.048 366.72 17.288 366.816 ;
      RECT 0.048 367.488 17.288 367.584 ;
      RECT 0.048 368.256 17.288 368.352 ;
      RECT 0.048 369.024 17.288 369.12 ;
      RECT 0.048 369.792 17.288 369.888 ;
      RECT 0.048 370.56 17.288 370.656 ;
      RECT 0.048 371.328 17.288 371.424 ;
      RECT 0.048 372.096 17.288 372.192 ;
      RECT 0.048 372.864 17.288 372.96 ;
      RECT 0.048 373.632 17.288 373.728 ;
      RECT 0.048 374.4 17.288 374.496 ;
      RECT 0.048 375.168 17.288 375.264 ;
      RECT 0.048 375.936 17.288 376.032 ;
      RECT 0.048 376.704 17.288 376.8 ;
      RECT 0.048 377.472 17.288 377.568 ;
      RECT 0.048 378.24 17.288 378.336 ;
      RECT 0.048 379.008 17.288 379.104 ;
      RECT 0.048 379.776 17.288 379.872 ;
      RECT 0.048 380.544 17.288 380.64 ;
      RECT 0.048 381.312 17.288 381.408 ;
      RECT 0.048 382.08 17.288 382.176 ;
      RECT 0.048 382.848 17.288 382.944 ;
      RECT 0.048 383.616 17.288 383.712 ;
      RECT 0.048 384.384 17.288 384.48 ;
      RECT 0.048 385.152 17.288 385.248 ;
      RECT 0.048 385.92 17.288 386.016 ;
      RECT 0.048 386.688 17.288 386.784 ;
      RECT 0.048 387.456 17.288 387.552 ;
      RECT 0.048 388.224 17.288 388.32 ;
      RECT 0.048 388.992 17.288 389.088 ;
      RECT 0.048 389.76 17.288 389.856 ;
      RECT 0.048 390.528 17.288 390.624 ;
      RECT 0.048 391.296 17.288 391.392 ;
      RECT 0.048 392.064 17.288 392.16 ;
      RECT 0.048 392.832 17.288 392.928 ;
      RECT 0.048 393.6 17.288 393.696 ;
      RECT 0.048 394.368 17.288 394.464 ;
      RECT 0.048 395.136 17.288 395.232 ;
      RECT 0.048 395.904 17.288 396 ;
      RECT 0.048 396.672 17.288 396.768 ;
      RECT 0.048 397.44 17.288 397.536 ;
      RECT 0.048 398.208 17.288 398.304 ;
      RECT 0.048 398.976 17.288 399.072 ;
      RECT 0.048 399.744 17.288 399.84 ;
      RECT 0.048 400.512 17.288 400.608 ;
      RECT 0.048 401.28 17.288 401.376 ;
      RECT 0.048 402.048 17.288 402.144 ;
      RECT 0.048 402.816 17.288 402.912 ;
      RECT 0.048 403.584 17.288 403.68 ;
      RECT 0.048 404.352 17.288 404.448 ;
      RECT 0.048 405.12 17.288 405.216 ;
      RECT 0.048 405.888 17.288 405.984 ;
      RECT 0.048 406.656 17.288 406.752 ;
      RECT 0.048 407.424 17.288 407.52 ;
      RECT 0.048 408.192 17.288 408.288 ;
      RECT 0.048 408.96 17.288 409.056 ;
      RECT 0.048 409.728 17.288 409.824 ;
      RECT 0.048 410.496 17.288 410.592 ;
      RECT 0.048 411.264 17.288 411.36 ;
      RECT 0.048 412.032 17.288 412.128 ;
      RECT 0.048 412.8 17.288 412.896 ;
      RECT 0.048 413.568 17.288 413.664 ;
      RECT 0.048 414.336 17.288 414.432 ;
      RECT 0.048 415.104 17.288 415.2 ;
      RECT 0.048 415.872 17.288 415.968 ;
      RECT 0.048 416.64 17.288 416.736 ;
      RECT 0.048 417.408 17.288 417.504 ;
      RECT 0.048 418.176 17.288 418.272 ;
      RECT 0.048 418.944 17.288 419.04 ;
      RECT 0.048 419.712 17.288 419.808 ;
      RECT 0.048 420.48 17.288 420.576 ;
      RECT 0.048 421.248 17.288 421.344 ;
      RECT 0.048 422.016 17.288 422.112 ;
      RECT 0.048 422.784 17.288 422.88 ;
      RECT 0.048 423.552 17.288 423.648 ;
      RECT 0.048 424.32 17.288 424.416 ;
      RECT 0.048 425.088 17.288 425.184 ;
      RECT 0.048 425.856 17.288 425.952 ;
      RECT 0.048 426.624 17.288 426.72 ;
      RECT 0.048 427.392 17.288 427.488 ;
      RECT 0.048 428.16 17.288 428.256 ;
      RECT 0.048 428.928 17.288 429.024 ;
      RECT 0.048 429.696 17.288 429.792 ;
      RECT 0.048 430.464 17.288 430.56 ;
      RECT 0.048 431.232 17.288 431.328 ;
      RECT 0.048 432 17.288 432.096 ;
      RECT 0.048 432.768 17.288 432.864 ;
      RECT 0.048 433.536 17.288 433.632 ;
      RECT 0.048 434.304 17.288 434.4 ;
      RECT 0.048 435.072 17.288 435.168 ;
      RECT 0.048 435.84 17.288 435.936 ;
      RECT 0.048 436.608 17.288 436.704 ;
      RECT 0.048 437.376 17.288 437.472 ;
      RECT 0.048 438.144 17.288 438.24 ;
      RECT 0.048 438.912 17.288 439.008 ;
      RECT 0.048 439.68 17.288 439.776 ;
      RECT 0.048 440.448 17.288 440.544 ;
      RECT 0.048 441.216 17.288 441.312 ;
      RECT 0.048 441.984 17.288 442.08 ;
      RECT 0.048 442.752 17.288 442.848 ;
      RECT 0.048 443.52 17.288 443.616 ;
      RECT 0.048 444.288 17.288 444.384 ;
      RECT 0.048 445.056 17.288 445.152 ;
      RECT 0.048 445.824 17.288 445.92 ;
      RECT 0.048 446.592 17.288 446.688 ;
      RECT 0.048 447.36 17.288 447.456 ;
      RECT 0.048 448.128 17.288 448.224 ;
      RECT 0.048 448.896 17.288 448.992 ;
      RECT 0.048 449.664 17.288 449.76 ;
      RECT 0.048 450.432 17.288 450.528 ;
      RECT 0.048 451.2 17.288 451.296 ;
      RECT 0.048 451.968 17.288 452.064 ;
      RECT 0.048 452.736 17.288 452.832 ;
      RECT 0.048 453.504 17.288 453.6 ;
      RECT 0.048 454.272 17.288 454.368 ;
      RECT 0.048 455.04 17.288 455.136 ;
      RECT 0.048 455.808 17.288 455.904 ;
      RECT 0.048 456.576 17.288 456.672 ;
      RECT 0.048 457.344 17.288 457.44 ;
      RECT 0.048 458.112 17.288 458.208 ;
      RECT 0.048 458.88 17.288 458.976 ;
      RECT 0.048 459.648 17.288 459.744 ;
      RECT 0.048 460.416 17.288 460.512 ;
      RECT 0.048 461.184 17.288 461.28 ;
      RECT 0.048 461.952 17.288 462.048 ;
      RECT 0.048 462.72 17.288 462.816 ;
      RECT 0.048 463.488 17.288 463.584 ;
      RECT 0.048 464.256 17.288 464.352 ;
      RECT 0.048 465.024 17.288 465.12 ;
      RECT 0.048 465.792 17.288 465.888 ;
      RECT 0.048 466.56 17.288 466.656 ;
      RECT 0.048 467.328 17.288 467.424 ;
      RECT 0.048 468.096 17.288 468.192 ;
      RECT 0.048 468.864 17.288 468.96 ;
      RECT 0.048 469.632 17.288 469.728 ;
      RECT 0.048 470.4 17.288 470.496 ;
      RECT 0.048 471.168 17.288 471.264 ;
      RECT 0.048 471.936 17.288 472.032 ;
      RECT 0.048 472.704 17.288 472.8 ;
      RECT 0.048 473.472 17.288 473.568 ;
      RECT 0.048 474.24 17.288 474.336 ;
      RECT 0.048 475.008 17.288 475.104 ;
      RECT 0.048 475.776 17.288 475.872 ;
      RECT 0.048 476.544 17.288 476.64 ;
      RECT 0.048 477.312 17.288 477.408 ;
      RECT 0.048 478.08 17.288 478.176 ;
      RECT 0.048 478.848 17.288 478.944 ;
      RECT 0.048 479.616 17.288 479.712 ;
      RECT 0.048 480.384 17.288 480.48 ;
      RECT 0.048 481.152 17.288 481.248 ;
      RECT 0.048 481.92 17.288 482.016 ;
      RECT 0.048 482.688 17.288 482.784 ;
      RECT 0.048 483.456 17.288 483.552 ;
      RECT 0.048 484.224 17.288 484.32 ;
      RECT 0.048 484.992 17.288 485.088 ;
      RECT 0.048 485.76 17.288 485.856 ;
      RECT 0.048 486.528 17.288 486.624 ;
      RECT 0.048 487.296 17.288 487.392 ;
      RECT 0.048 488.064 17.288 488.16 ;
      RECT 0.048 488.832 17.288 488.928 ;
      RECT 0.048 489.6 17.288 489.696 ;
      RECT 0.048 490.368 17.288 490.464 ;
      RECT 0.048 491.136 17.288 491.232 ;
      RECT 0.048 491.904 17.288 492 ;
      RECT 0.048 492.672 17.288 492.768 ;
      RECT 0.048 493.44 17.288 493.536 ;
      RECT 0.048 494.208 17.288 494.304 ;
      RECT 0.048 494.976 17.288 495.072 ;
      RECT 0.048 495.744 17.288 495.84 ;
      RECT 0.048 496.512 17.288 496.608 ;
      RECT 0.048 497.28 17.288 497.376 ;
      RECT 0.048 498.048 17.288 498.144 ;
      RECT 0.048 498.816 17.288 498.912 ;
      RECT 0.048 499.584 17.288 499.68 ;
      RECT 0.048 500.352 17.288 500.448 ;
      RECT 0.048 501.12 17.288 501.216 ;
      RECT 0.048 501.888 17.288 501.984 ;
      RECT 0.048 502.656 17.288 502.752 ;
      RECT 0.048 503.424 17.288 503.52 ;
      RECT 0.048 504.192 17.288 504.288 ;
      RECT 0.048 504.96 17.288 505.056 ;
      RECT 0.048 505.728 17.288 505.824 ;
      RECT 0.048 506.496 17.288 506.592 ;
      RECT 0.048 507.264 17.288 507.36 ;
      RECT 0.048 508.032 17.288 508.128 ;
      RECT 0.048 508.8 17.288 508.896 ;
      RECT 0.048 509.568 17.288 509.664 ;
      RECT 0.048 510.336 17.288 510.432 ;
      RECT 0.048 511.104 17.288 511.2 ;
      RECT 0.048 511.872 17.288 511.968 ;
      RECT 0.048 512.64 17.288 512.736 ;
      RECT 0.048 513.408 17.288 513.504 ;
      RECT 0.048 514.176 17.288 514.272 ;
      RECT 0.048 514.944 17.288 515.04 ;
      RECT 0.048 515.712 17.288 515.808 ;
      RECT 0.048 516.48 17.288 516.576 ;
      RECT 0.048 517.248 17.288 517.344 ;
      RECT 0.048 518.016 17.288 518.112 ;
      RECT 0.048 518.784 17.288 518.88 ;
      RECT 0.048 519.552 17.288 519.648 ;
      RECT 0.048 520.32 17.288 520.416 ;
      RECT 0.048 521.088 17.288 521.184 ;
      RECT 0.048 521.856 17.288 521.952 ;
      RECT 0.048 522.624 17.288 522.72 ;
      RECT 0.048 523.392 17.288 523.488 ;
      RECT 0.048 524.16 17.288 524.256 ;
      RECT 0.048 524.928 17.288 525.024 ;
      RECT 0.048 525.696 17.288 525.792 ;
      RECT 0.048 526.464 17.288 526.56 ;
      RECT 0.048 527.232 17.288 527.328 ;
      RECT 0.048 528 17.288 528.096 ;
      RECT 0.048 528.768 17.288 528.864 ;
      RECT 0.048 529.536 17.288 529.632 ;
      RECT 0.048 530.304 17.288 530.4 ;
      RECT 0.048 531.072 17.288 531.168 ;
      RECT 0.048 531.84 17.288 531.936 ;
      RECT 0.048 532.608 17.288 532.704 ;
      RECT 0.048 533.376 17.288 533.472 ;
      RECT 0.048 534.144 17.288 534.24 ;
      RECT 0.048 534.912 17.288 535.008 ;
      RECT 0.048 535.68 17.288 535.776 ;
      RECT 0.048 536.448 17.288 536.544 ;
      RECT 0.048 537.216 17.288 537.312 ;
      RECT 0.048 537.984 17.288 538.08 ;
      RECT 0.048 538.752 17.288 538.848 ;
      RECT 0.048 539.52 17.288 539.616 ;
      RECT 0.048 540.288 17.288 540.384 ;
      RECT 0.048 541.056 17.288 541.152 ;
      RECT 0.048 541.824 17.288 541.92 ;
      RECT 0.048 542.592 17.288 542.688 ;
      RECT 0.048 543.36 17.288 543.456 ;
      RECT 0.048 544.128 17.288 544.224 ;
      RECT 0.048 544.896 17.288 544.992 ;
      RECT 0.048 545.664 17.288 545.76 ;
      RECT 0.048 546.432 17.288 546.528 ;
      RECT 0.048 547.2 17.288 547.296 ;
      RECT 0.048 547.968 17.288 548.064 ;
      RECT 0.048 548.736 17.288 548.832 ;
      RECT 0.048 549.504 17.288 549.6 ;
      RECT 0.048 550.272 17.288 550.368 ;
      RECT 0.048 551.04 17.288 551.136 ;
      RECT 0.048 551.808 17.288 551.904 ;
      RECT 0.048 552.576 17.288 552.672 ;
      RECT 0.048 553.344 17.288 553.44 ;
      RECT 0.048 554.112 17.288 554.208 ;
      RECT 0.048 554.88 17.288 554.976 ;
      RECT 0.048 555.648 17.288 555.744 ;
      RECT 0.048 556.416 17.288 556.512 ;
      RECT 0.048 557.184 17.288 557.28 ;
      RECT 0.048 557.952 17.288 558.048 ;
      RECT 0.048 558.72 17.288 558.816 ;
      RECT 0.048 559.488 17.288 559.584 ;
      RECT 0.048 560.256 17.288 560.352 ;
      RECT 0.048 561.024 17.288 561.12 ;
      RECT 0.048 561.792 17.288 561.888 ;
      RECT 0.048 562.56 17.288 562.656 ;
      RECT 0.048 563.328 17.288 563.424 ;
      RECT 0.048 564.096 17.288 564.192 ;
      RECT 0.048 564.864 17.288 564.96 ;
      RECT 0.048 565.632 17.288 565.728 ;
      RECT 0.048 566.4 17.288 566.496 ;
      RECT 0.048 567.168 17.288 567.264 ;
      RECT 0.048 567.936 17.288 568.032 ;
      RECT 0.048 568.704 17.288 568.8 ;
      RECT 0.048 569.472 17.288 569.568 ;
      RECT 0.048 570.24 17.288 570.336 ;
      RECT 0.048 571.008 17.288 571.104 ;
      RECT 0.048 571.776 17.288 571.872 ;
      RECT 0.048 572.544 17.288 572.64 ;
      RECT 0.048 573.312 17.288 573.408 ;
      RECT 0.048 574.08 17.288 574.176 ;
      RECT 0.048 574.848 17.288 574.944 ;
      RECT 0.048 575.616 17.288 575.712 ;
      RECT 0.048 576.384 17.288 576.48 ;
      RECT 0.048 577.152 17.288 577.248 ;
      RECT 0.048 577.92 17.288 578.016 ;
      RECT 0.048 578.688 17.288 578.784 ;
      RECT 0.048 579.456 17.288 579.552 ;
      RECT 0.048 580.224 17.288 580.32 ;
      RECT 0.048 580.992 17.288 581.088 ;
      RECT 0.048 581.76 17.288 581.856 ;
      RECT 0.048 582.528 17.288 582.624 ;
      RECT 0.048 583.296 17.288 583.392 ;
      RECT 0.048 584.064 17.288 584.16 ;
      RECT 0.048 584.832 17.288 584.928 ;
      RECT 0.048 585.6 17.288 585.696 ;
      RECT 0.048 586.368 17.288 586.464 ;
      RECT 0.048 587.136 17.288 587.232 ;
      RECT 0.048 587.904 17.288 588 ;
      RECT 0.048 588.672 17.288 588.768 ;
      RECT 0.048 589.44 17.288 589.536 ;
      RECT 0.048 590.208 17.288 590.304 ;
      RECT 0.048 590.976 17.288 591.072 ;
      RECT 0.048 591.744 17.288 591.84 ;
      RECT 0.048 592.512 17.288 592.608 ;
      RECT 0.048 593.28 17.288 593.376 ;
      RECT 0.048 594.048 17.288 594.144 ;
      RECT 0.048 594.816 17.288 594.912 ;
      RECT 0.048 595.584 17.288 595.68 ;
      RECT 0.048 596.352 17.288 596.448 ;
      RECT 0.048 597.12 17.288 597.216 ;
      RECT 0.048 597.888 17.288 597.984 ;
      RECT 0.048 598.656 17.288 598.752 ;
      RECT 0.048 599.424 17.288 599.52 ;
      RECT 0.048 600.192 17.288 600.288 ;
      RECT 0.048 600.96 17.288 601.056 ;
      RECT 0.048 601.728 17.288 601.824 ;
      RECT 0.048 602.496 17.288 602.592 ;
      RECT 0.048 603.264 17.288 603.36 ;
      RECT 0.048 604.032 17.288 604.128 ;
      RECT 0.048 604.8 17.288 604.896 ;
      RECT 0.048 605.568 17.288 605.664 ;
      RECT 0.048 606.336 17.288 606.432 ;
      RECT 0.048 607.104 17.288 607.2 ;
      RECT 0.048 607.872 17.288 607.968 ;
      RECT 0.048 608.64 17.288 608.736 ;
      RECT 0.048 609.408 17.288 609.504 ;
      RECT 0.048 610.176 17.288 610.272 ;
      RECT 0.048 610.944 17.288 611.04 ;
      RECT 0.048 611.712 17.288 611.808 ;
      RECT 0.048 612.48 17.288 612.576 ;
      RECT 0.048 613.248 17.288 613.344 ;
      RECT 0.048 614.016 17.288 614.112 ;
      RECT 0.048 614.784 17.288 614.88 ;
      RECT 0.048 615.552 17.288 615.648 ;
      RECT 0.048 616.32 17.288 616.416 ;
      RECT 0.048 617.088 17.288 617.184 ;
      RECT 0.048 617.856 17.288 617.952 ;
      RECT 0.048 618.624 17.288 618.72 ;
      RECT 0.048 619.392 17.288 619.488 ;
      RECT 0.048 620.16 17.288 620.256 ;
      RECT 0.048 620.928 17.288 621.024 ;
      RECT 0.048 621.696 17.288 621.792 ;
      RECT 0.048 622.464 17.288 622.56 ;
      RECT 0.048 623.232 17.288 623.328 ;
      RECT 0.048 624 17.288 624.096 ;
      RECT 0.048 624.768 17.288 624.864 ;
      RECT 0.048 625.536 17.288 625.632 ;
      RECT 0.048 626.304 17.288 626.4 ;
      RECT 0.048 627.072 17.288 627.168 ;
      RECT 0.048 627.84 17.288 627.936 ;
      RECT 0.048 628.608 17.288 628.704 ;
      RECT 0.048 629.376 17.288 629.472 ;
      RECT 0.048 630.144 17.288 630.24 ;
      RECT 0.048 630.912 17.288 631.008 ;
      RECT 0.048 631.68 17.288 631.776 ;
      RECT 0.048 632.448 17.288 632.544 ;
      RECT 0.048 633.216 17.288 633.312 ;
      RECT 0.048 633.984 17.288 634.08 ;
      RECT 0.048 634.752 17.288 634.848 ;
      RECT 0.048 635.52 17.288 635.616 ;
      RECT 0.048 636.288 17.288 636.384 ;
      RECT 0.048 637.056 17.288 637.152 ;
      RECT 0.048 637.824 17.288 637.92 ;
      RECT 0.048 638.592 17.288 638.688 ;
      RECT 0.048 639.36 17.288 639.456 ;
      RECT 0.048 640.128 17.288 640.224 ;
      RECT 0.048 640.896 17.288 640.992 ;
      RECT 0.048 641.664 17.288 641.76 ;
      RECT 0.048 642.432 17.288 642.528 ;
      RECT 0.048 643.2 17.288 643.296 ;
      RECT 0.048 643.968 17.288 644.064 ;
      RECT 0.048 644.736 17.288 644.832 ;
      RECT 0.048 645.504 17.288 645.6 ;
      RECT 0.048 646.272 17.288 646.368 ;
      RECT 0.048 647.04 17.288 647.136 ;
      RECT 0.048 647.808 17.288 647.904 ;
      RECT 0.048 648.576 17.288 648.672 ;
      RECT 0.048 649.344 17.288 649.44 ;
      RECT 0.048 650.112 17.288 650.208 ;
      RECT 0.048 650.88 17.288 650.976 ;
      RECT 0.048 651.648 17.288 651.744 ;
      RECT 0.048 652.416 17.288 652.512 ;
      RECT 0.048 653.184 17.288 653.28 ;
      RECT 0.048 653.952 17.288 654.048 ;
      RECT 0.048 654.72 17.288 654.816 ;
      RECT 0.048 655.488 17.288 655.584 ;
      RECT 0.048 656.256 17.288 656.352 ;
      RECT 0.048 657.024 17.288 657.12 ;
      RECT 0.048 657.792 17.288 657.888 ;
      RECT 0.048 658.56 17.288 658.656 ;
      RECT 0.048 659.328 17.288 659.424 ;
      RECT 0.048 660.096 17.288 660.192 ;
      RECT 0.048 660.864 17.288 660.96 ;
      RECT 0.048 661.632 17.288 661.728 ;
      RECT 0.048 662.4 17.288 662.496 ;
      RECT 0.048 663.168 17.288 663.264 ;
      RECT 0.048 663.936 17.288 664.032 ;
      RECT 0.048 664.704 17.288 664.8 ;
      RECT 0.048 665.472 17.288 665.568 ;
      RECT 0.048 666.24 17.288 666.336 ;
      RECT 0.048 667.008 17.288 667.104 ;
      RECT 0.048 667.776 17.288 667.872 ;
      RECT 0.048 668.544 17.288 668.64 ;
      RECT 0.048 669.312 17.288 669.408 ;
      RECT 0.048 670.08 17.288 670.176 ;
      RECT 0.048 670.848 17.288 670.944 ;
      RECT 0.048 671.616 17.288 671.712 ;
      RECT 0.048 672.384 17.288 672.48 ;
      RECT 0.048 673.152 17.288 673.248 ;
      RECT 0.048 673.92 17.288 674.016 ;
      RECT 0.048 674.688 17.288 674.784 ;
      RECT 0.048 675.456 17.288 675.552 ;
      RECT 0.048 676.224 17.288 676.32 ;
      RECT 0.048 676.992 17.288 677.088 ;
      RECT 0.048 677.76 17.288 677.856 ;
      RECT 0.048 678.528 17.288 678.624 ;
      RECT 0.048 679.296 17.288 679.392 ;
      RECT 0.048 680.064 17.288 680.16 ;
      RECT 0.048 680.832 17.288 680.928 ;
      RECT 0.048 681.6 17.288 681.696 ;
      RECT 0.048 682.368 17.288 682.464 ;
      RECT 0.048 683.136 17.288 683.232 ;
      RECT 0.048 683.904 17.288 684 ;
      RECT 0.048 684.672 17.288 684.768 ;
      RECT 0.048 685.44 17.288 685.536 ;
      RECT 0.048 686.208 17.288 686.304 ;
      RECT 0.048 686.976 17.288 687.072 ;
      RECT 0.048 687.744 17.288 687.84 ;
      RECT 0.048 688.512 17.288 688.608 ;
      RECT 0.048 689.28 17.288 689.376 ;
      RECT 0.048 690.048 17.288 690.144 ;
      RECT 0.048 690.816 17.288 690.912 ;
      RECT 0.048 691.584 17.288 691.68 ;
      RECT 0.048 692.352 17.288 692.448 ;
      RECT 0.048 693.12 17.288 693.216 ;
      RECT 0.048 693.888 17.288 693.984 ;
      RECT 0.048 694.656 17.288 694.752 ;
      RECT 0.048 695.424 17.288 695.52 ;
    END
  END VDD
  OBS
    LAYER M1_m ;
    RECT 0 0 17.336 696.121 ;
    LAYER M2_m ;
    RECT 0 0 17.336 696.121 ;
    LAYER M3_m ;
    RECT 0 0 17.336 696.121 ;
  END
END ht_asap7_rocketgemmini_mem_1_ext_upper

END LIBRARY
